VERSION 5.8 ;
BUSBITCHARS "[]" ;
DIVIDERCHAR "/" ;
UNITS
    DATABASE MICRONS 1000 ;
END UNITS

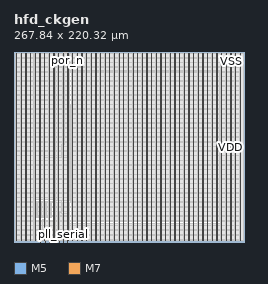
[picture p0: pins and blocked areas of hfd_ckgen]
MACRO hfd_ckgen
  FOREIGN hfd_ckgen 0 0 ;
  CLASS BLOCK ;
  SIZE 267.84 BY 220.32 ;
  PIN pll_hbm
    DIRECTION OUTPUT ;
    USE SIGNAL ;
    PORT
      LAYER M5 ;
        RECT  48.048 0 48.072 0.084 ;
    END
  END pll_hbm
  PIN pll_link
    DIRECTION OUTPUT ;
    USE SIGNAL ;
    PORT
      LAYER M5 ;
        RECT  62.448 0 62.472 0.084 ;
    END
  END pll_link
  PIN pll_serial
    DIRECTION OUTPUT ;
    USE SIGNAL ;
    PORT
      LAYER M5 ;
        RECT  57.648 0 57.672 0.084 ;
    END
  END pll_serial
  PIN pll_stream
    DIRECTION OUTPUT ;
    USE SIGNAL ;
    PORT
      LAYER M5 ;
        RECT  52.848 0 52.872 0.084 ;
    END
  END pll_stream
  PIN por_hbm
    DIRECTION OUTPUT ;
    USE SIGNAL ;
    PORT
      LAYER M5 ;
        RECT  31.152 0 31.176 0.084 ;
    END
  END por_hbm
  PIN por_link
    DIRECTION OUTPUT ;
    USE SIGNAL ;
    PORT
      LAYER M5 ;
        RECT  40.848 0 40.872 0.084 ;
    END
  END por_link
  PIN por_n
    DIRECTION INPUT ;
    USE SIGNAL ;
    PORT
      LAYER M5 ;
        RECT  62.352 220.236 62.376 220.32 ;
    END
  END por_n
  PIN por_serial
    DIRECTION OUTPUT ;
    USE SIGNAL ;
    PORT
      LAYER M5 ;
        RECT  36.24 0 36.264 0.084 ;
    END
  END por_serial
  PIN por_stream
    DIRECTION OUTPUT ;
    USE SIGNAL ;
    PORT
      LAYER M5 ;
        RECT  35.952 0 35.976 0.084 ;
    END
  END por_stream
  PIN refclk
    DIRECTION INPUT ;
    USE SIGNAL ;
    PORT
      LAYER M5 ;
        RECT  57.552 220.236 57.576 220.32 ;
    END
  END refclk
  PIN VDD
    DIRECTION INOUT ;
    USE POWER ;
    PORT
      LAYER M7 ;
        RECT  256.816 2.151 257.104 218.169 ;
        RECT  246.016 2.151 246.304 218.169 ;
        RECT  235.216 2.151 235.504 218.169 ;
        RECT  224.416 2.151 224.704 218.169 ;
        RECT  213.616 2.151 213.904 218.169 ;
        RECT  202.816 2.151 203.104 218.169 ;
        RECT  192.016 2.151 192.304 218.169 ;
        RECT  181.216 2.151 181.504 218.169 ;
        RECT  170.416 2.151 170.704 218.169 ;
        RECT  159.616 2.151 159.904 218.169 ;
        RECT  148.816 2.151 149.104 218.169 ;
        RECT  138.016 2.151 138.304 218.169 ;
        RECT  127.216 2.151 127.504 218.169 ;
        RECT  116.416 2.151 116.704 218.169 ;
        RECT  105.616 2.151 105.904 218.169 ;
        RECT  94.816 2.151 95.104 218.169 ;
        RECT  84.016 2.151 84.304 218.169 ;
        RECT  73.216 2.151 73.504 218.169 ;
        RECT  62.416 2.151 62.704 218.169 ;
        RECT  51.616 2.151 51.904 218.169 ;
        RECT  40.816 2.151 41.104 218.169 ;
        RECT  30.016 2.151 30.304 218.169 ;
        RECT  19.216 2.151 19.504 218.169 ;
        RECT  8.416 2.151 8.704 218.169 ;
    END
  END VDD
  PIN VSS
    DIRECTION INOUT ;
    USE GROUND ;
    PORT
      LAYER M7 ;
        RECT  262.216 2.151 262.504 218.169 ;
        RECT  251.416 2.151 251.704 218.169 ;
        RECT  240.616 2.151 240.904 218.169 ;
        RECT  229.816 2.151 230.104 218.169 ;
        RECT  219.016 2.151 219.304 218.169 ;
        RECT  208.216 2.151 208.504 218.169 ;
        RECT  197.416 2.151 197.704 218.169 ;
        RECT  186.616 2.151 186.904 218.169 ;
        RECT  175.816 2.151 176.104 218.169 ;
        RECT  165.016 2.151 165.304 218.169 ;
        RECT  154.216 2.151 154.504 218.169 ;
        RECT  143.416 2.151 143.704 218.169 ;
        RECT  132.616 2.151 132.904 218.169 ;
        RECT  121.816 2.151 122.104 218.169 ;
        RECT  111.016 2.151 111.304 218.169 ;
        RECT  100.216 2.151 100.504 218.169 ;
        RECT  89.416 2.151 89.704 218.169 ;
        RECT  78.616 2.151 78.904 218.169 ;
        RECT  67.816 2.151 68.104 218.169 ;
        RECT  57.016 2.151 57.304 218.169 ;
        RECT  46.216 2.151 46.504 218.169 ;
        RECT  35.416 2.151 35.704 218.169 ;
        RECT  24.616 2.151 24.904 218.169 ;
        RECT  13.816 2.151 14.104 218.169 ;
        RECT  3.016 2.151 3.304 218.169 ;
    END
  END VSS
  OBS
    LAYER RVTN ;
     RECT  2.16 2.16 265.68 2.295 ;
     RECT  2.16 2.565 265.68 2.835 ;
     RECT  2.16 3.105 265.68 3.375 ;
     RECT  2.16 3.645 265.68 3.915 ;
     RECT  2.16 4.185 265.68 4.455 ;
     RECT  2.16 4.725 265.68 4.995 ;
     RECT  2.16 5.265 265.68 5.535 ;
     RECT  2.16 5.805 265.68 6.075 ;
     RECT  2.16 6.345 265.68 6.615 ;
     RECT  2.16 6.885 265.68 7.155 ;
     RECT  2.16 7.425 265.68 7.695 ;
     RECT  2.16 7.965 265.68 8.235 ;
     RECT  2.16 8.505 265.68 8.775 ;
     RECT  2.16 9.045 265.68 9.315 ;
     RECT  2.16 9.585 265.68 9.855 ;
     RECT  2.16 10.125 265.68 10.395 ;
     RECT  2.16 10.665 265.68 10.935 ;
     RECT  2.16 11.205 265.68 11.475 ;
     RECT  2.16 11.745 265.68 12.015 ;
     RECT  2.16 12.285 265.68 12.555 ;
     RECT  2.16 12.825 265.68 13.095 ;
     RECT  2.16 13.365 265.68 13.635 ;
     RECT  2.16 13.905 265.68 14.175 ;
     RECT  2.16 14.445 265.68 14.715 ;
     RECT  2.16 14.985 265.68 15.255 ;
     RECT  2.16 15.525 265.68 15.795 ;
     RECT  2.16 16.065 265.68 16.335 ;
     RECT  2.16 16.605 265.68 16.875 ;
     RECT  2.16 17.145 265.68 17.415 ;
     RECT  2.16 17.685 265.68 17.955 ;
     RECT  2.16 18.225 265.68 18.495 ;
     RECT  2.16 18.765 265.68 19.035 ;
     RECT  2.16 19.305 265.68 19.575 ;
     RECT  2.16 19.845 265.68 20.115 ;
     RECT  2.16 20.385 265.68 20.655 ;
     RECT  2.16 20.925 265.68 21.195 ;
     RECT  2.16 21.465 265.68 21.6 ;
     RECT  2.16 21.6 64.044 21.735 ;
     RECT  240.948 21.6 265.68 21.735 ;
     RECT  2.16 22.005 64.044 22.275 ;
     RECT  240.948 22.005 265.68 22.275 ;
     RECT  2.16 22.545 64.044 22.815 ;
     RECT  240.948 22.545 265.68 22.815 ;
     RECT  2.16 23.085 64.044 23.355 ;
     RECT  240.948 23.085 265.68 23.355 ;
     RECT  2.16 23.625 64.044 23.76 ;
     RECT  2.16 23.76 22.14 23.895 ;
     RECT  47.844 23.76 64.044 23.895 ;
     RECT  240.948 23.625 265.68 23.895 ;
     RECT  2.16 24.165 22.14 24.435 ;
     RECT  47.844 24.165 64.044 24.435 ;
     RECT  240.948 24.165 265.68 24.435 ;
     RECT  2.16 24.705 22.14 24.975 ;
     RECT  47.844 24.705 64.044 24.975 ;
     RECT  240.948 24.705 265.68 24.975 ;
     RECT  2.16 25.245 22.14 25.515 ;
     RECT  47.844 25.245 64.044 25.515 ;
     RECT  240.948 25.245 265.68 25.515 ;
     RECT  2.16 25.785 22.14 26.055 ;
     RECT  47.844 25.785 64.044 26.055 ;
     RECT  240.948 25.785 265.68 26.055 ;
     RECT  2.16 26.325 22.14 26.595 ;
     RECT  47.844 26.325 64.044 26.595 ;
     RECT  240.948 26.325 265.68 26.595 ;
     RECT  2.16 26.865 22.14 27.135 ;
     RECT  47.844 26.865 64.044 27.135 ;
     RECT  240.948 26.865 265.68 27.135 ;
     RECT  2.16 27.405 22.14 27.675 ;
     RECT  47.844 27.405 64.044 27.675 ;
     RECT  240.948 27.405 265.68 27.675 ;
     RECT  2.16 27.945 22.14 28.215 ;
     RECT  26.352 28.08 43.632 28.215 ;
     RECT  47.844 27.945 64.044 28.215 ;
     RECT  240.948 27.945 265.68 28.215 ;
     RECT  2.16 28.485 22.14 28.755 ;
     RECT  26.352 28.485 43.632 28.755 ;
     RECT  47.844 28.485 64.044 28.755 ;
     RECT  240.948 28.485 265.68 28.755 ;
     RECT  2.16 29.025 22.14 29.295 ;
     RECT  26.352 29.025 43.632 29.295 ;
     RECT  47.844 29.025 64.044 29.295 ;
     RECT  240.948 29.025 265.68 29.295 ;
     RECT  2.16 29.565 22.14 29.835 ;
     RECT  26.352 29.565 43.632 29.835 ;
     RECT  47.844 29.565 64.044 29.835 ;
     RECT  240.948 29.565 265.68 29.835 ;
     RECT  2.16 30.105 22.14 30.375 ;
     RECT  26.352 30.105 43.632 30.375 ;
     RECT  47.844 30.105 64.044 30.375 ;
     RECT  240.948 30.105 265.68 30.375 ;
     RECT  2.16 30.645 22.14 30.915 ;
     RECT  26.352 30.645 43.632 30.915 ;
     RECT  47.844 30.645 64.044 30.915 ;
     RECT  240.948 30.645 265.68 30.915 ;
     RECT  2.16 31.185 22.14 31.455 ;
     RECT  26.352 31.185 43.632 31.455 ;
     RECT  47.844 31.185 64.044 31.455 ;
     RECT  240.948 31.185 265.68 31.455 ;
     RECT  2.16 31.725 22.14 31.995 ;
     RECT  26.352 31.725 43.632 31.995 ;
     RECT  47.844 31.725 64.044 31.995 ;
     RECT  240.948 31.725 265.68 31.995 ;
     RECT  2.16 32.265 22.14 32.535 ;
     RECT  26.352 32.265 43.632 32.535 ;
     RECT  47.844 32.265 64.044 32.535 ;
     RECT  240.948 32.265 265.68 32.535 ;
     RECT  2.16 32.805 22.14 33.075 ;
     RECT  26.352 32.805 43.632 33.075 ;
     RECT  47.844 32.805 64.044 33.075 ;
     RECT  240.948 32.805 265.68 33.075 ;
     RECT  2.16 33.345 22.14 33.615 ;
     RECT  26.352 33.345 43.632 33.615 ;
     RECT  47.844 33.345 64.044 33.615 ;
     RECT  240.948 33.345 265.68 33.615 ;
     RECT  2.16 33.885 22.14 34.155 ;
     RECT  26.352 33.885 43.632 34.155 ;
     RECT  47.844 33.885 64.044 34.155 ;
     RECT  240.948 33.885 265.68 34.155 ;
     RECT  2.16 34.425 22.14 34.695 ;
     RECT  26.352 34.425 43.632 34.695 ;
     RECT  47.844 34.425 64.044 34.695 ;
     RECT  240.948 34.425 265.68 34.695 ;
     RECT  2.16 34.965 22.14 35.235 ;
     RECT  26.352 34.965 43.632 35.235 ;
     RECT  47.844 34.965 64.044 35.235 ;
     RECT  240.948 34.965 265.68 35.235 ;
     RECT  2.16 35.505 22.14 35.775 ;
     RECT  26.352 35.505 43.632 35.775 ;
     RECT  47.844 35.505 64.044 35.775 ;
     RECT  240.948 35.505 265.68 35.775 ;
     RECT  2.16 36.045 22.14 36.315 ;
     RECT  26.352 36.045 43.632 36.315 ;
     RECT  47.844 36.045 64.044 36.315 ;
     RECT  240.948 36.045 265.68 36.315 ;
     RECT  2.16 36.585 22.14 36.855 ;
     RECT  26.352 36.585 43.632 36.855 ;
     RECT  47.844 36.585 64.044 36.855 ;
     RECT  240.948 36.585 265.68 36.855 ;
     RECT  2.16 37.125 22.14 37.395 ;
     RECT  26.352 37.125 43.632 37.395 ;
     RECT  47.844 37.125 64.044 37.395 ;
     RECT  240.948 37.125 265.68 37.395 ;
     RECT  2.16 37.665 22.14 37.935 ;
     RECT  26.352 37.665 43.632 37.935 ;
     RECT  47.844 37.665 64.044 37.935 ;
     RECT  240.948 37.665 265.68 37.935 ;
     RECT  2.16 38.205 22.14 38.475 ;
     RECT  26.352 38.205 43.632 38.475 ;
     RECT  47.844 38.205 64.044 38.475 ;
     RECT  240.948 38.205 265.68 38.475 ;
     RECT  2.16 38.745 22.14 39.015 ;
     RECT  26.352 38.745 43.632 39.015 ;
     RECT  47.844 38.745 64.044 39.015 ;
     RECT  240.948 38.745 265.68 39.015 ;
     RECT  2.16 39.285 22.14 39.555 ;
     RECT  26.352 39.285 43.632 39.555 ;
     RECT  47.844 39.285 64.044 39.555 ;
     RECT  240.948 39.285 265.68 39.555 ;
     RECT  2.16 39.825 22.14 40.095 ;
     RECT  26.352 39.825 43.632 40.095 ;
     RECT  47.844 39.825 64.044 40.095 ;
     RECT  240.948 39.825 265.68 40.095 ;
     RECT  2.16 40.365 22.14 40.635 ;
     RECT  26.352 40.365 43.632 40.635 ;
     RECT  47.844 40.365 64.044 40.635 ;
     RECT  240.948 40.365 265.68 40.635 ;
     RECT  2.16 40.905 22.14 41.175 ;
     RECT  26.352 40.905 43.632 41.175 ;
     RECT  47.844 40.905 64.044 41.175 ;
     RECT  240.948 40.905 265.68 41.175 ;
     RECT  2.16 41.445 22.14 41.715 ;
     RECT  26.352 41.445 43.632 41.715 ;
     RECT  47.844 41.445 64.044 41.715 ;
     RECT  240.948 41.445 265.68 41.715 ;
     RECT  2.16 41.985 22.14 42.255 ;
     RECT  26.352 41.985 43.632 42.255 ;
     RECT  47.844 41.985 64.044 42.255 ;
     RECT  240.948 41.985 265.68 42.255 ;
     RECT  2.16 42.525 22.14 42.795 ;
     RECT  26.352 42.525 43.632 42.795 ;
     RECT  47.844 42.525 64.044 42.795 ;
     RECT  240.948 42.525 265.68 42.795 ;
     RECT  2.16 43.065 22.14 43.335 ;
     RECT  26.352 43.065 43.632 43.335 ;
     RECT  47.844 43.065 64.044 43.335 ;
     RECT  240.948 43.065 265.68 43.335 ;
     RECT  2.16 43.605 22.14 43.875 ;
     RECT  26.352 43.605 43.632 43.875 ;
     RECT  47.844 43.605 64.044 43.875 ;
     RECT  240.948 43.605 265.68 43.875 ;
     RECT  2.16 44.145 22.14 44.415 ;
     RECT  26.352 44.145 43.632 44.415 ;
     RECT  47.844 44.145 64.044 44.415 ;
     RECT  240.948 44.145 265.68 44.415 ;
     RECT  2.16 44.685 22.14 44.955 ;
     RECT  26.352 44.685 43.632 44.955 ;
     RECT  47.844 44.685 64.044 44.955 ;
     RECT  240.948 44.685 265.68 44.955 ;
     RECT  26.352 45.225 43.632 45.36 ;
     RECT  2.16 45.225 22.14 45.495 ;
     RECT  47.844 45.225 64.044 45.495 ;
     RECT  240.948 45.225 265.68 45.495 ;
     RECT  2.16 45.765 22.14 46.035 ;
     RECT  47.844 45.765 64.044 46.035 ;
     RECT  240.948 45.765 265.68 46.035 ;
     RECT  2.16 46.305 22.14 46.575 ;
     RECT  47.844 46.305 64.044 46.575 ;
     RECT  240.948 46.305 265.68 46.575 ;
     RECT  2.16 46.845 22.14 47.115 ;
     RECT  47.844 46.845 64.044 47.115 ;
     RECT  240.948 46.845 265.68 47.115 ;
     RECT  2.16 47.385 22.14 47.655 ;
     RECT  47.844 47.385 64.044 47.655 ;
     RECT  240.948 47.385 265.68 47.655 ;
     RECT  2.16 47.925 22.14 48.195 ;
     RECT  47.844 47.925 64.044 48.195 ;
     RECT  240.948 47.925 265.68 48.195 ;
     RECT  2.16 48.465 22.14 48.735 ;
     RECT  47.844 48.465 64.044 48.735 ;
     RECT  240.948 48.465 265.68 48.735 ;
     RECT  2.16 49.005 22.14 49.275 ;
     RECT  47.844 49.005 64.044 49.275 ;
     RECT  240.948 49.005 265.68 49.275 ;
     RECT  2.16 49.545 22.14 49.68 ;
     RECT  47.844 49.545 64.044 49.68 ;
     RECT  2.16 49.68 64.044 49.815 ;
     RECT  240.948 49.545 265.68 49.815 ;
     RECT  2.16 50.085 64.044 50.355 ;
     RECT  240.948 50.085 265.68 50.355 ;
     RECT  2.16 50.625 64.044 50.895 ;
     RECT  240.948 50.625 265.68 50.895 ;
     RECT  2.16 51.165 64.044 51.435 ;
     RECT  240.948 51.165 265.68 51.435 ;
     RECT  2.16 51.705 64.044 51.975 ;
     RECT  240.948 51.705 265.68 51.975 ;
     RECT  2.16 52.245 64.044 52.515 ;
     RECT  240.948 52.245 265.68 52.515 ;
     RECT  2.16 52.785 64.044 53.055 ;
     RECT  240.948 52.785 265.68 53.055 ;
     RECT  2.16 53.325 64.044 53.595 ;
     RECT  240.948 53.325 265.68 53.595 ;
     RECT  2.16 53.865 64.044 54.135 ;
     RECT  240.948 53.865 265.68 54.135 ;
     RECT  2.16 54.405 64.044 54.675 ;
     RECT  240.948 54.405 265.68 54.675 ;
     RECT  2.16 54.945 64.044 55.215 ;
     RECT  240.948 54.945 265.68 55.215 ;
     RECT  2.16 55.485 64.044 55.755 ;
     RECT  240.948 55.485 265.68 55.755 ;
     RECT  2.16 56.025 64.044 56.295 ;
     RECT  240.948 56.025 265.68 56.295 ;
     RECT  2.16 56.565 64.044 56.835 ;
     RECT  240.948 56.565 265.68 56.835 ;
     RECT  2.16 57.105 64.044 57.375 ;
     RECT  240.948 57.105 265.68 57.375 ;
     RECT  2.16 57.645 64.044 57.915 ;
     RECT  240.948 57.645 265.68 57.915 ;
     RECT  2.16 58.185 64.044 58.455 ;
     RECT  240.948 58.185 265.68 58.455 ;
     RECT  2.16 58.725 64.044 58.995 ;
     RECT  240.948 58.725 265.68 58.995 ;
     RECT  2.16 59.265 64.044 59.535 ;
     RECT  240.948 59.265 265.68 59.535 ;
     RECT  2.16 59.805 64.044 60.075 ;
     RECT  240.948 59.805 265.68 60.075 ;
     RECT  2.16 60.345 64.044 60.615 ;
     RECT  240.948 60.345 265.68 60.615 ;
     RECT  2.16 60.885 64.044 61.155 ;
     RECT  240.948 60.885 265.68 61.155 ;
     RECT  2.16 61.425 64.044 61.695 ;
     RECT  240.948 61.425 265.68 61.695 ;
     RECT  2.16 61.965 64.044 62.235 ;
     RECT  240.948 61.965 265.68 62.235 ;
     RECT  2.16 62.505 64.044 62.775 ;
     RECT  240.948 62.505 265.68 62.775 ;
     RECT  2.16 63.045 64.044 63.315 ;
     RECT  240.948 63.045 265.68 63.315 ;
     RECT  2.16 63.585 64.044 63.855 ;
     RECT  240.948 63.585 265.68 63.855 ;
     RECT  2.16 64.125 64.044 64.395 ;
     RECT  240.948 64.125 265.68 64.395 ;
     RECT  2.16 64.665 64.044 64.935 ;
     RECT  240.948 64.665 265.68 64.935 ;
     RECT  2.16 65.205 64.044 65.475 ;
     RECT  240.948 65.205 265.68 65.475 ;
     RECT  2.16 65.745 64.044 66.015 ;
     RECT  240.948 65.745 265.68 66.015 ;
     RECT  2.16 66.285 64.044 66.555 ;
     RECT  240.948 66.285 265.68 66.555 ;
     RECT  2.16 66.825 64.044 67.095 ;
     RECT  240.948 66.825 265.68 67.095 ;
     RECT  2.16 67.365 64.044 67.635 ;
     RECT  240.948 67.365 265.68 67.635 ;
     RECT  2.16 67.905 64.044 68.175 ;
     RECT  240.948 67.905 265.68 68.175 ;
     RECT  2.16 68.445 64.044 68.715 ;
     RECT  240.948 68.445 265.68 68.715 ;
     RECT  2.16 68.985 64.044 69.255 ;
     RECT  240.948 68.985 265.68 69.255 ;
     RECT  2.16 69.525 64.044 69.795 ;
     RECT  240.948 69.525 265.68 69.795 ;
     RECT  2.16 70.065 64.044 70.335 ;
     RECT  240.948 70.065 265.68 70.335 ;
     RECT  2.16 70.605 64.044 70.875 ;
     RECT  240.948 70.605 265.68 70.875 ;
     RECT  2.16 71.145 64.044 71.415 ;
     RECT  240.948 71.145 265.68 71.415 ;
     RECT  2.16 71.685 64.044 71.955 ;
     RECT  240.948 71.685 265.68 71.955 ;
     RECT  2.16 72.225 64.044 72.495 ;
     RECT  240.948 72.225 265.68 72.495 ;
     RECT  2.16 72.765 64.044 73.035 ;
     RECT  240.948 72.765 265.68 73.035 ;
     RECT  2.16 73.305 64.044 73.575 ;
     RECT  240.948 73.305 265.68 73.575 ;
     RECT  2.16 73.845 64.044 74.115 ;
     RECT  240.948 73.845 265.68 74.115 ;
     RECT  2.16 74.385 64.044 74.655 ;
     RECT  240.948 74.385 265.68 74.655 ;
     RECT  2.16 74.925 64.044 75.195 ;
     RECT  240.948 74.925 265.68 75.195 ;
     RECT  2.16 75.465 64.044 75.735 ;
     RECT  240.948 75.465 265.68 75.735 ;
     RECT  2.16 76.005 64.044 76.275 ;
     RECT  240.948 76.005 265.68 76.275 ;
     RECT  2.16 76.545 64.044 76.815 ;
     RECT  240.948 76.545 265.68 76.815 ;
     RECT  2.16 77.085 64.044 77.355 ;
     RECT  240.948 77.085 265.68 77.355 ;
     RECT  2.16 77.625 64.044 77.895 ;
     RECT  240.948 77.625 265.68 77.895 ;
     RECT  2.16 78.165 64.044 78.435 ;
     RECT  240.948 78.165 265.68 78.435 ;
     RECT  2.16 78.705 64.044 78.975 ;
     RECT  240.948 78.705 265.68 78.975 ;
     RECT  2.16 79.245 64.044 79.515 ;
     RECT  240.948 79.245 265.68 79.515 ;
     RECT  2.16 79.785 64.044 80.055 ;
     RECT  240.948 79.785 265.68 80.055 ;
     RECT  2.16 80.325 64.044 80.595 ;
     RECT  240.948 80.325 265.68 80.595 ;
     RECT  2.16 80.865 64.044 81.135 ;
     RECT  240.948 80.865 265.68 81.135 ;
     RECT  2.16 81.405 64.044 81.675 ;
     RECT  240.948 81.405 265.68 81.675 ;
     RECT  2.16 81.945 64.044 82.215 ;
     RECT  240.948 81.945 265.68 82.215 ;
     RECT  2.16 82.485 64.044 82.755 ;
     RECT  240.948 82.485 265.68 82.755 ;
     RECT  2.16 83.025 64.044 83.295 ;
     RECT  240.948 83.025 265.68 83.295 ;
     RECT  2.16 83.565 64.044 83.835 ;
     RECT  240.948 83.565 265.68 83.835 ;
     RECT  2.16 84.105 64.044 84.375 ;
     RECT  240.948 84.105 265.68 84.375 ;
     RECT  2.16 84.645 64.044 84.915 ;
     RECT  240.948 84.645 265.68 84.915 ;
     RECT  2.16 85.185 64.044 85.455 ;
     RECT  240.948 85.185 265.68 85.455 ;
     RECT  2.16 85.725 64.044 85.995 ;
     RECT  240.948 85.725 265.68 85.995 ;
     RECT  2.16 86.265 64.044 86.535 ;
     RECT  240.948 86.265 265.68 86.535 ;
     RECT  2.16 86.805 64.044 87.075 ;
     RECT  240.948 86.805 265.68 87.075 ;
     RECT  2.16 87.345 64.044 87.615 ;
     RECT  240.948 87.345 265.68 87.615 ;
     RECT  2.16 87.885 64.044 88.155 ;
     RECT  240.948 87.885 265.68 88.155 ;
     RECT  2.16 88.425 64.044 88.695 ;
     RECT  240.948 88.425 265.68 88.695 ;
     RECT  2.16 88.965 64.044 89.235 ;
     RECT  240.948 88.965 265.68 89.235 ;
     RECT  2.16 89.505 64.044 89.775 ;
     RECT  240.948 89.505 265.68 89.775 ;
     RECT  2.16 90.045 64.044 90.315 ;
     RECT  240.948 90.045 265.68 90.315 ;
     RECT  2.16 90.585 64.044 90.855 ;
     RECT  240.948 90.585 265.68 90.855 ;
     RECT  2.16 91.125 64.044 91.395 ;
     RECT  240.948 91.125 265.68 91.395 ;
     RECT  2.16 91.665 64.044 91.935 ;
     RECT  240.948 91.665 265.68 91.935 ;
     RECT  2.16 92.205 64.044 92.475 ;
     RECT  240.948 92.205 265.68 92.475 ;
     RECT  2.16 92.745 64.044 93.015 ;
     RECT  240.948 92.745 265.68 93.015 ;
     RECT  2.16 93.285 64.044 93.555 ;
     RECT  240.948 93.285 265.68 93.555 ;
     RECT  2.16 93.825 64.044 94.095 ;
     RECT  240.948 93.825 265.68 94.095 ;
     RECT  2.16 94.365 64.044 94.635 ;
     RECT  240.948 94.365 265.68 94.635 ;
     RECT  2.16 94.905 64.044 95.175 ;
     RECT  240.948 94.905 265.68 95.175 ;
     RECT  2.16 95.445 64.044 95.715 ;
     RECT  240.948 95.445 265.68 95.715 ;
     RECT  2.16 95.985 64.044 96.255 ;
     RECT  240.948 95.985 265.68 96.255 ;
     RECT  2.16 96.525 64.044 96.795 ;
     RECT  240.948 96.525 265.68 96.795 ;
     RECT  2.16 97.065 64.044 97.335 ;
     RECT  240.948 97.065 265.68 97.335 ;
     RECT  2.16 97.605 64.044 97.875 ;
     RECT  240.948 97.605 265.68 97.875 ;
     RECT  2.16 98.145 64.044 98.415 ;
     RECT  240.948 98.145 265.68 98.415 ;
     RECT  2.16 98.685 64.044 98.955 ;
     RECT  240.948 98.685 265.68 98.955 ;
     RECT  2.16 99.225 64.044 99.495 ;
     RECT  240.948 99.225 265.68 99.495 ;
     RECT  2.16 99.765 64.044 100.035 ;
     RECT  240.948 99.765 265.68 100.035 ;
     RECT  2.16 100.305 64.044 100.575 ;
     RECT  240.948 100.305 265.68 100.575 ;
     RECT  2.16 100.845 64.044 101.115 ;
     RECT  240.948 100.845 265.68 101.115 ;
     RECT  2.16 101.385 64.044 101.655 ;
     RECT  240.948 101.385 265.68 101.655 ;
     RECT  2.16 101.925 64.044 102.195 ;
     RECT  240.948 101.925 265.68 102.195 ;
     RECT  2.16 102.465 64.044 102.735 ;
     RECT  240.948 102.465 265.68 102.735 ;
     RECT  2.16 103.005 64.044 103.275 ;
     RECT  240.948 103.005 265.68 103.275 ;
     RECT  2.16 103.545 64.044 103.815 ;
     RECT  240.948 103.545 265.68 103.815 ;
     RECT  2.16 104.085 64.044 104.355 ;
     RECT  240.948 104.085 265.68 104.355 ;
     RECT  2.16 104.625 64.044 104.895 ;
     RECT  240.948 104.625 265.68 104.895 ;
     RECT  2.16 105.165 64.044 105.435 ;
     RECT  240.948 105.165 265.68 105.435 ;
     RECT  2.16 105.705 64.044 105.975 ;
     RECT  240.948 105.705 265.68 105.975 ;
     RECT  2.16 106.245 64.044 106.515 ;
     RECT  240.948 106.245 265.68 106.515 ;
     RECT  2.16 106.785 64.044 107.055 ;
     RECT  240.948 106.785 265.68 107.055 ;
     RECT  2.16 107.325 64.044 107.595 ;
     RECT  240.948 107.325 265.68 107.595 ;
     RECT  2.16 107.865 64.044 108.135 ;
     RECT  240.948 107.865 265.68 108.135 ;
     RECT  2.16 108.405 64.044 108.675 ;
     RECT  240.948 108.405 265.68 108.675 ;
     RECT  2.16 108.945 64.044 109.215 ;
     RECT  240.948 108.945 265.68 109.215 ;
     RECT  2.16 109.485 64.044 109.755 ;
     RECT  240.948 109.485 265.68 109.755 ;
     RECT  2.16 110.025 64.044 110.295 ;
     RECT  240.948 110.025 265.68 110.295 ;
     RECT  2.16 110.565 64.044 110.835 ;
     RECT  240.948 110.565 265.68 110.835 ;
     RECT  2.16 111.105 64.044 111.375 ;
     RECT  240.948 111.105 265.68 111.375 ;
     RECT  2.16 111.645 64.044 111.915 ;
     RECT  240.948 111.645 265.68 111.915 ;
     RECT  2.16 112.185 64.044 112.455 ;
     RECT  240.948 112.185 265.68 112.455 ;
     RECT  2.16 112.725 64.044 112.995 ;
     RECT  240.948 112.725 265.68 112.995 ;
     RECT  2.16 113.265 64.044 113.535 ;
     RECT  240.948 113.265 265.68 113.535 ;
     RECT  2.16 113.805 64.044 114.075 ;
     RECT  240.948 113.805 265.68 114.075 ;
     RECT  2.16 114.345 64.044 114.615 ;
     RECT  240.948 114.345 265.68 114.615 ;
     RECT  2.16 114.885 64.044 115.155 ;
     RECT  240.948 114.885 265.68 115.155 ;
     RECT  2.16 115.425 64.044 115.695 ;
     RECT  240.948 115.425 265.68 115.695 ;
     RECT  2.16 115.965 64.044 116.235 ;
     RECT  240.948 115.965 265.68 116.235 ;
     RECT  2.16 116.505 64.044 116.775 ;
     RECT  240.948 116.505 265.68 116.775 ;
     RECT  2.16 117.045 64.044 117.315 ;
     RECT  240.948 117.045 265.68 117.315 ;
     RECT  2.16 117.585 64.044 117.855 ;
     RECT  240.948 117.585 265.68 117.855 ;
     RECT  2.16 118.125 64.044 118.395 ;
     RECT  240.948 118.125 265.68 118.395 ;
     RECT  2.16 118.665 64.044 118.935 ;
     RECT  240.948 118.665 265.68 118.935 ;
     RECT  2.16 119.205 64.044 119.475 ;
     RECT  240.948 119.205 265.68 119.475 ;
     RECT  2.16 119.745 64.044 120.015 ;
     RECT  240.948 119.745 265.68 120.015 ;
     RECT  2.16 120.285 64.044 120.555 ;
     RECT  240.948 120.285 265.68 120.555 ;
     RECT  2.16 120.825 64.044 121.095 ;
     RECT  240.948 120.825 265.68 121.095 ;
     RECT  2.16 121.365 64.044 121.635 ;
     RECT  240.948 121.365 265.68 121.635 ;
     RECT  2.16 121.905 64.044 122.175 ;
     RECT  240.948 121.905 265.68 122.175 ;
     RECT  2.16 122.445 64.044 122.715 ;
     RECT  240.948 122.445 265.68 122.715 ;
     RECT  2.16 122.985 64.044 123.255 ;
     RECT  240.948 122.985 265.68 123.255 ;
     RECT  2.16 123.525 64.044 123.795 ;
     RECT  240.948 123.525 265.68 123.795 ;
     RECT  2.16 124.065 64.044 124.335 ;
     RECT  240.948 124.065 265.68 124.335 ;
     RECT  2.16 124.605 64.044 124.875 ;
     RECT  240.948 124.605 265.68 124.875 ;
     RECT  2.16 125.145 64.044 125.415 ;
     RECT  240.948 125.145 265.68 125.415 ;
     RECT  2.16 125.685 64.044 125.955 ;
     RECT  240.948 125.685 265.68 125.955 ;
     RECT  2.16 126.225 64.044 126.495 ;
     RECT  240.948 126.225 265.68 126.495 ;
     RECT  2.16 126.765 64.044 127.035 ;
     RECT  240.948 126.765 265.68 127.035 ;
     RECT  2.16 127.305 64.044 127.575 ;
     RECT  240.948 127.305 265.68 127.575 ;
     RECT  2.16 127.845 64.044 128.115 ;
     RECT  240.948 127.845 265.68 128.115 ;
     RECT  2.16 128.385 64.044 128.655 ;
     RECT  240.948 128.385 265.68 128.655 ;
     RECT  2.16 128.925 64.044 129.195 ;
     RECT  240.948 128.925 265.68 129.195 ;
     RECT  2.16 129.465 64.044 129.735 ;
     RECT  240.948 129.465 265.68 129.735 ;
     RECT  2.16 130.005 64.044 130.275 ;
     RECT  240.948 130.005 265.68 130.275 ;
     RECT  2.16 130.545 64.044 130.815 ;
     RECT  240.948 130.545 265.68 130.815 ;
     RECT  2.16 131.085 64.044 131.355 ;
     RECT  240.948 131.085 265.68 131.355 ;
     RECT  2.16 131.625 64.044 131.895 ;
     RECT  240.948 131.625 265.68 131.895 ;
     RECT  2.16 132.165 64.044 132.435 ;
     RECT  240.948 132.165 265.68 132.435 ;
     RECT  2.16 132.705 64.044 132.975 ;
     RECT  240.948 132.705 265.68 132.975 ;
     RECT  2.16 133.245 64.044 133.515 ;
     RECT  240.948 133.245 265.68 133.515 ;
     RECT  2.16 133.785 64.044 134.055 ;
     RECT  240.948 133.785 265.68 134.055 ;
     RECT  2.16 134.325 64.044 134.595 ;
     RECT  240.948 134.325 265.68 134.595 ;
     RECT  2.16 134.865 64.044 135.135 ;
     RECT  240.948 134.865 265.68 135.135 ;
     RECT  2.16 135.405 64.044 135.675 ;
     RECT  240.948 135.405 265.68 135.675 ;
     RECT  2.16 135.945 64.044 136.215 ;
     RECT  240.948 135.945 265.68 136.215 ;
     RECT  2.16 136.485 64.044 136.755 ;
     RECT  240.948 136.485 265.68 136.755 ;
     RECT  2.16 137.025 64.044 137.295 ;
     RECT  240.948 137.025 265.68 137.295 ;
     RECT  2.16 137.565 64.044 137.835 ;
     RECT  240.948 137.565 265.68 137.835 ;
     RECT  2.16 138.105 64.044 138.375 ;
     RECT  240.948 138.105 265.68 138.375 ;
     RECT  2.16 138.645 64.044 138.915 ;
     RECT  240.948 138.645 265.68 138.915 ;
     RECT  2.16 139.185 64.044 139.455 ;
     RECT  240.948 139.185 265.68 139.455 ;
     RECT  2.16 139.725 64.044 139.995 ;
     RECT  240.948 139.725 265.68 139.995 ;
     RECT  2.16 140.265 64.044 140.535 ;
     RECT  240.948 140.265 265.68 140.535 ;
     RECT  2.16 140.805 64.044 141.075 ;
     RECT  240.948 140.805 265.68 141.075 ;
     RECT  2.16 141.345 64.044 141.615 ;
     RECT  240.948 141.345 265.68 141.615 ;
     RECT  2.16 141.885 64.044 142.155 ;
     RECT  240.948 141.885 265.68 142.155 ;
     RECT  2.16 142.425 64.044 142.695 ;
     RECT  240.948 142.425 265.68 142.695 ;
     RECT  2.16 142.965 64.044 143.235 ;
     RECT  240.948 142.965 265.68 143.235 ;
     RECT  2.16 143.505 64.044 143.775 ;
     RECT  240.948 143.505 265.68 143.775 ;
     RECT  2.16 144.045 64.044 144.315 ;
     RECT  240.948 144.045 265.68 144.315 ;
     RECT  2.16 144.585 64.044 144.855 ;
     RECT  240.948 144.585 265.68 144.855 ;
     RECT  2.16 145.125 64.044 145.395 ;
     RECT  240.948 145.125 265.68 145.395 ;
     RECT  2.16 145.665 64.044 145.935 ;
     RECT  240.948 145.665 265.68 145.935 ;
     RECT  2.16 146.205 64.044 146.475 ;
     RECT  240.948 146.205 265.68 146.475 ;
     RECT  2.16 146.745 64.044 147.015 ;
     RECT  240.948 146.745 265.68 147.015 ;
     RECT  2.16 147.285 64.044 147.555 ;
     RECT  240.948 147.285 265.68 147.555 ;
     RECT  2.16 147.825 64.044 148.095 ;
     RECT  240.948 147.825 265.68 148.095 ;
     RECT  2.16 148.365 64.044 148.635 ;
     RECT  240.948 148.365 265.68 148.635 ;
     RECT  2.16 148.905 64.044 149.175 ;
     RECT  240.948 148.905 265.68 149.175 ;
     RECT  2.16 149.445 64.044 149.715 ;
     RECT  240.948 149.445 265.68 149.715 ;
     RECT  2.16 149.985 64.044 150.255 ;
     RECT  240.948 149.985 265.68 150.255 ;
     RECT  2.16 150.525 64.044 150.795 ;
     RECT  240.948 150.525 265.68 150.795 ;
     RECT  2.16 151.065 64.044 151.335 ;
     RECT  240.948 151.065 265.68 151.335 ;
     RECT  2.16 151.605 64.044 151.875 ;
     RECT  240.948 151.605 265.68 151.875 ;
     RECT  2.16 152.145 64.044 152.415 ;
     RECT  240.948 152.145 265.68 152.415 ;
     RECT  2.16 152.685 64.044 152.955 ;
     RECT  240.948 152.685 265.68 152.955 ;
     RECT  2.16 153.225 64.044 153.495 ;
     RECT  240.948 153.225 265.68 153.495 ;
     RECT  2.16 153.765 64.044 154.035 ;
     RECT  240.948 153.765 265.68 154.035 ;
     RECT  2.16 154.305 64.044 154.575 ;
     RECT  240.948 154.305 265.68 154.575 ;
     RECT  2.16 154.845 64.044 155.115 ;
     RECT  240.948 154.845 265.68 155.115 ;
     RECT  2.16 155.385 64.044 155.655 ;
     RECT  240.948 155.385 265.68 155.655 ;
     RECT  2.16 155.925 64.044 156.195 ;
     RECT  240.948 155.925 265.68 156.195 ;
     RECT  2.16 156.465 64.044 156.735 ;
     RECT  240.948 156.465 265.68 156.735 ;
     RECT  2.16 157.005 64.044 157.275 ;
     RECT  240.948 157.005 265.68 157.275 ;
     RECT  2.16 157.545 64.044 157.815 ;
     RECT  240.948 157.545 265.68 157.815 ;
     RECT  2.16 158.085 64.044 158.355 ;
     RECT  240.948 158.085 265.68 158.355 ;
     RECT  2.16 158.625 64.044 158.895 ;
     RECT  240.948 158.625 265.68 158.895 ;
     RECT  2.16 159.165 64.044 159.435 ;
     RECT  240.948 159.165 265.68 159.435 ;
     RECT  2.16 159.705 64.044 159.975 ;
     RECT  240.948 159.705 265.68 159.975 ;
     RECT  2.16 160.245 64.044 160.515 ;
     RECT  240.948 160.245 265.68 160.515 ;
     RECT  2.16 160.785 64.044 161.055 ;
     RECT  240.948 160.785 265.68 161.055 ;
     RECT  2.16 161.325 64.044 161.595 ;
     RECT  240.948 161.325 265.68 161.595 ;
     RECT  2.16 161.865 64.044 162.135 ;
     RECT  240.948 161.865 265.68 162.135 ;
     RECT  2.16 162.405 64.044 162.675 ;
     RECT  240.948 162.405 265.68 162.675 ;
     RECT  2.16 162.945 64.044 163.215 ;
     RECT  240.948 162.945 265.68 163.215 ;
     RECT  2.16 163.485 64.044 163.755 ;
     RECT  240.948 163.485 265.68 163.755 ;
     RECT  2.16 164.025 64.044 164.295 ;
     RECT  240.948 164.025 265.68 164.295 ;
     RECT  2.16 164.565 64.044 164.835 ;
     RECT  240.948 164.565 265.68 164.835 ;
     RECT  2.16 165.105 64.044 165.375 ;
     RECT  240.948 165.105 265.68 165.375 ;
     RECT  2.16 165.645 64.044 165.915 ;
     RECT  240.948 165.645 265.68 165.915 ;
     RECT  2.16 166.185 64.044 166.455 ;
     RECT  240.948 166.185 265.68 166.455 ;
     RECT  2.16 166.725 64.044 166.995 ;
     RECT  240.948 166.725 265.68 166.995 ;
     RECT  2.16 167.265 64.044 167.535 ;
     RECT  240.948 167.265 265.68 167.535 ;
     RECT  2.16 167.805 64.044 168.075 ;
     RECT  240.948 167.805 265.68 168.075 ;
     RECT  2.16 168.345 64.044 168.615 ;
     RECT  240.948 168.345 265.68 168.615 ;
     RECT  2.16 168.885 64.044 169.155 ;
     RECT  240.948 168.885 265.68 169.155 ;
     RECT  2.16 169.425 64.044 169.695 ;
     RECT  240.948 169.425 265.68 169.695 ;
     RECT  2.16 169.965 64.044 170.235 ;
     RECT  240.948 169.965 265.68 170.235 ;
     RECT  2.16 170.505 64.044 170.775 ;
     RECT  240.948 170.505 265.68 170.775 ;
     RECT  2.16 171.045 64.044 171.315 ;
     RECT  240.948 171.045 265.68 171.315 ;
     RECT  2.16 171.585 64.044 171.855 ;
     RECT  240.948 171.585 265.68 171.855 ;
     RECT  2.16 172.125 64.044 172.395 ;
     RECT  240.948 172.125 265.68 172.395 ;
     RECT  2.16 172.665 64.044 172.935 ;
     RECT  240.948 172.665 265.68 172.935 ;
     RECT  2.16 173.205 64.044 173.475 ;
     RECT  240.948 173.205 265.68 173.475 ;
     RECT  2.16 173.745 64.044 174.015 ;
     RECT  240.948 173.745 265.68 174.015 ;
     RECT  2.16 174.285 64.044 174.555 ;
     RECT  240.948 174.285 265.68 174.555 ;
     RECT  2.16 174.825 64.044 175.095 ;
     RECT  240.948 174.825 265.68 175.095 ;
     RECT  2.16 175.365 64.044 175.635 ;
     RECT  240.948 175.365 265.68 175.635 ;
     RECT  2.16 175.905 64.044 176.175 ;
     RECT  240.948 175.905 265.68 176.175 ;
     RECT  2.16 176.445 64.044 176.715 ;
     RECT  240.948 176.445 265.68 176.715 ;
     RECT  2.16 176.985 64.044 177.255 ;
     RECT  240.948 176.985 265.68 177.255 ;
     RECT  2.16 177.525 64.044 177.795 ;
     RECT  240.948 177.525 265.68 177.795 ;
     RECT  2.16 178.065 64.044 178.335 ;
     RECT  240.948 178.065 265.68 178.335 ;
     RECT  2.16 178.605 64.044 178.875 ;
     RECT  240.948 178.605 265.68 178.875 ;
     RECT  2.16 179.145 64.044 179.415 ;
     RECT  240.948 179.145 265.68 179.415 ;
     RECT  2.16 179.685 64.044 179.955 ;
     RECT  240.948 179.685 265.68 179.955 ;
     RECT  2.16 180.225 64.044 180.495 ;
     RECT  240.948 180.225 265.68 180.495 ;
     RECT  2.16 180.765 64.044 181.035 ;
     RECT  240.948 180.765 265.68 181.035 ;
     RECT  2.16 181.305 64.044 181.575 ;
     RECT  240.948 181.305 265.68 181.575 ;
     RECT  2.16 181.845 64.044 182.115 ;
     RECT  240.948 181.845 265.68 182.115 ;
     RECT  2.16 182.385 64.044 182.655 ;
     RECT  240.948 182.385 265.68 182.655 ;
     RECT  2.16 182.925 64.044 183.195 ;
     RECT  240.948 182.925 265.68 183.195 ;
     RECT  2.16 183.465 64.044 183.735 ;
     RECT  240.948 183.465 265.68 183.735 ;
     RECT  2.16 184.005 64.044 184.275 ;
     RECT  240.948 184.005 265.68 184.275 ;
     RECT  2.16 184.545 64.044 184.815 ;
     RECT  240.948 184.545 265.68 184.815 ;
     RECT  2.16 185.085 64.044 185.355 ;
     RECT  240.948 185.085 265.68 185.355 ;
     RECT  2.16 185.625 64.044 185.895 ;
     RECT  240.948 185.625 265.68 185.895 ;
     RECT  2.16 186.165 64.044 186.435 ;
     RECT  240.948 186.165 265.68 186.435 ;
     RECT  2.16 186.705 64.044 186.975 ;
     RECT  240.948 186.705 265.68 186.975 ;
     RECT  2.16 187.245 64.044 187.515 ;
     RECT  240.948 187.245 265.68 187.515 ;
     RECT  2.16 187.785 64.044 188.055 ;
     RECT  240.948 187.785 265.68 188.055 ;
     RECT  2.16 188.325 64.044 188.595 ;
     RECT  240.948 188.325 265.68 188.595 ;
     RECT  2.16 188.865 64.044 189.135 ;
     RECT  240.948 188.865 265.68 189.135 ;
     RECT  2.16 189.405 64.044 189.675 ;
     RECT  240.948 189.405 265.68 189.675 ;
     RECT  2.16 189.945 64.044 190.215 ;
     RECT  240.948 189.945 265.68 190.215 ;
     RECT  2.16 190.485 64.044 190.755 ;
     RECT  240.948 190.485 265.68 190.755 ;
     RECT  2.16 191.025 64.044 191.295 ;
     RECT  240.948 191.025 265.68 191.295 ;
     RECT  2.16 191.565 64.044 191.835 ;
     RECT  240.948 191.565 265.68 191.835 ;
     RECT  2.16 192.105 64.044 192.375 ;
     RECT  240.948 192.105 265.68 192.375 ;
     RECT  2.16 192.645 64.044 192.915 ;
     RECT  240.948 192.645 265.68 192.915 ;
     RECT  2.16 193.185 64.044 193.455 ;
     RECT  240.948 193.185 265.68 193.455 ;
     RECT  2.16 193.725 64.044 193.995 ;
     RECT  240.948 193.725 265.68 193.995 ;
     RECT  2.16 194.265 64.044 194.535 ;
     RECT  240.948 194.265 265.68 194.535 ;
     RECT  2.16 194.805 64.044 195.075 ;
     RECT  240.948 194.805 265.68 195.075 ;
     RECT  2.16 195.345 64.044 195.615 ;
     RECT  240.948 195.345 265.68 195.615 ;
     RECT  2.16 195.885 64.044 196.155 ;
     RECT  240.948 195.885 265.68 196.155 ;
     RECT  2.16 196.425 64.044 196.695 ;
     RECT  240.948 196.425 265.68 196.695 ;
     RECT  2.16 196.965 64.044 197.235 ;
     RECT  240.948 196.965 265.68 197.235 ;
     RECT  2.16 197.505 64.044 197.775 ;
     RECT  240.948 197.505 265.68 197.775 ;
     RECT  2.16 198.045 64.044 198.315 ;
     RECT  240.948 198.045 265.68 198.315 ;
     RECT  2.16 198.585 64.044 198.72 ;
     RECT  240.948 198.585 265.68 198.72 ;
     RECT  2.16 198.72 265.68 198.855 ;
     RECT  2.16 199.125 265.68 199.395 ;
     RECT  2.16 199.665 265.68 199.935 ;
     RECT  2.16 200.205 265.68 200.475 ;
     RECT  2.16 200.745 265.68 201.015 ;
     RECT  2.16 201.285 265.68 201.555 ;
     RECT  2.16 201.825 265.68 202.095 ;
     RECT  2.16 202.365 265.68 202.635 ;
     RECT  2.16 202.905 265.68 203.175 ;
     RECT  2.16 203.445 265.68 203.715 ;
     RECT  2.16 203.985 265.68 204.255 ;
     RECT  2.16 204.525 265.68 204.795 ;
     RECT  2.16 205.065 265.68 205.335 ;
     RECT  2.16 205.605 265.68 205.875 ;
     RECT  2.16 206.145 265.68 206.415 ;
     RECT  2.16 206.685 265.68 206.955 ;
     RECT  2.16 207.225 265.68 207.495 ;
     RECT  2.16 207.765 265.68 208.035 ;
     RECT  2.16 208.305 265.68 208.575 ;
     RECT  2.16 208.845 265.68 209.115 ;
     RECT  2.16 209.385 265.68 209.655 ;
     RECT  2.16 209.925 265.68 210.195 ;
     RECT  2.16 210.465 265.68 210.735 ;
     RECT  2.16 211.005 265.68 211.275 ;
     RECT  2.16 211.545 265.68 211.815 ;
     RECT  2.16 212.085 265.68 212.355 ;
     RECT  2.16 212.625 265.68 212.895 ;
     RECT  2.16 213.165 265.68 213.435 ;
     RECT  2.16 213.705 265.68 213.975 ;
     RECT  2.16 214.245 265.68 214.515 ;
     RECT  2.16 214.785 265.68 215.055 ;
     RECT  2.16 215.325 265.68 215.595 ;
     RECT  2.16 215.865 265.68 216.135 ;
     RECT  2.16 216.405 265.68 216.675 ;
     RECT  2.16 216.945 265.68 217.215 ;
     RECT  2.16 217.485 265.68 217.755 ;
     RECT  2.16 218.025 265.68 218.16 ;
    LAYER RVTP ;
     RECT  2.16 2.295 265.68 2.565 ;
     RECT  2.16 2.835 265.68 3.105 ;
     RECT  2.16 3.375 265.68 3.645 ;
     RECT  2.16 3.915 265.68 4.185 ;
     RECT  2.16 4.455 265.68 4.725 ;
     RECT  2.16 4.995 265.68 5.265 ;
     RECT  2.16 5.535 265.68 5.805 ;
     RECT  2.16 6.075 265.68 6.345 ;
     RECT  2.16 6.615 265.68 6.885 ;
     RECT  2.16 7.155 265.68 7.425 ;
     RECT  2.16 7.695 265.68 7.965 ;
     RECT  2.16 8.235 265.68 8.505 ;
     RECT  2.16 8.775 265.68 9.045 ;
     RECT  2.16 9.315 265.68 9.585 ;
     RECT  2.16 9.855 265.68 10.125 ;
     RECT  2.16 10.395 265.68 10.665 ;
     RECT  2.16 10.935 265.68 11.205 ;
     RECT  2.16 11.475 265.68 11.745 ;
     RECT  2.16 12.015 265.68 12.285 ;
     RECT  2.16 12.555 265.68 12.825 ;
     RECT  2.16 13.095 265.68 13.365 ;
     RECT  2.16 13.635 265.68 13.905 ;
     RECT  2.16 14.175 265.68 14.445 ;
     RECT  2.16 14.715 265.68 14.985 ;
     RECT  2.16 15.255 265.68 15.525 ;
     RECT  2.16 15.795 265.68 16.065 ;
     RECT  2.16 16.335 265.68 16.605 ;
     RECT  2.16 16.875 265.68 17.145 ;
     RECT  2.16 17.415 265.68 17.685 ;
     RECT  2.16 17.955 265.68 18.225 ;
     RECT  2.16 18.495 265.68 18.765 ;
     RECT  2.16 19.035 265.68 19.305 ;
     RECT  2.16 19.575 265.68 19.845 ;
     RECT  2.16 20.115 265.68 20.385 ;
     RECT  2.16 20.655 265.68 20.925 ;
     RECT  2.16 21.195 265.68 21.465 ;
     RECT  2.16 21.735 64.044 22.005 ;
     RECT  240.948 21.735 265.68 22.005 ;
     RECT  2.16 22.275 64.044 22.545 ;
     RECT  240.948 22.275 265.68 22.545 ;
     RECT  2.16 22.815 64.044 23.085 ;
     RECT  240.948 22.815 265.68 23.085 ;
     RECT  2.16 23.355 64.044 23.625 ;
     RECT  240.948 23.355 265.68 23.625 ;
     RECT  2.16 23.895 22.14 24.165 ;
     RECT  47.844 23.895 64.044 24.165 ;
     RECT  240.948 23.895 265.68 24.165 ;
     RECT  2.16 24.435 22.14 24.705 ;
     RECT  47.844 24.435 64.044 24.705 ;
     RECT  240.948 24.435 265.68 24.705 ;
     RECT  2.16 24.975 22.14 25.245 ;
     RECT  47.844 24.975 64.044 25.245 ;
     RECT  240.948 24.975 265.68 25.245 ;
     RECT  2.16 25.515 22.14 25.785 ;
     RECT  47.844 25.515 64.044 25.785 ;
     RECT  240.948 25.515 265.68 25.785 ;
     RECT  2.16 26.055 22.14 26.325 ;
     RECT  47.844 26.055 64.044 26.325 ;
     RECT  240.948 26.055 265.68 26.325 ;
     RECT  2.16 26.595 22.14 26.865 ;
     RECT  47.844 26.595 64.044 26.865 ;
     RECT  240.948 26.595 265.68 26.865 ;
     RECT  2.16 27.135 22.14 27.405 ;
     RECT  47.844 27.135 64.044 27.405 ;
     RECT  240.948 27.135 265.68 27.405 ;
     RECT  2.16 27.675 22.14 27.945 ;
     RECT  47.844 27.675 64.044 27.945 ;
     RECT  240.948 27.675 265.68 27.945 ;
     RECT  2.16 28.215 22.14 28.485 ;
     RECT  26.352 28.215 43.632 28.485 ;
     RECT  47.844 28.215 64.044 28.485 ;
     RECT  240.948 28.215 265.68 28.485 ;
     RECT  2.16 28.755 22.14 29.025 ;
     RECT  26.352 28.755 43.632 29.025 ;
     RECT  47.844 28.755 64.044 29.025 ;
     RECT  240.948 28.755 265.68 29.025 ;
     RECT  2.16 29.295 22.14 29.565 ;
     RECT  26.352 29.295 43.632 29.565 ;
     RECT  47.844 29.295 64.044 29.565 ;
     RECT  240.948 29.295 265.68 29.565 ;
     RECT  2.16 29.835 22.14 30.105 ;
     RECT  26.352 29.835 43.632 30.105 ;
     RECT  47.844 29.835 64.044 30.105 ;
     RECT  240.948 29.835 265.68 30.105 ;
     RECT  2.16 30.375 22.14 30.645 ;
     RECT  26.352 30.375 43.632 30.645 ;
     RECT  47.844 30.375 64.044 30.645 ;
     RECT  240.948 30.375 265.68 30.645 ;
     RECT  2.16 30.915 22.14 31.185 ;
     RECT  26.352 30.915 43.632 31.185 ;
     RECT  47.844 30.915 64.044 31.185 ;
     RECT  240.948 30.915 265.68 31.185 ;
     RECT  2.16 31.455 22.14 31.725 ;
     RECT  26.352 31.455 43.632 31.725 ;
     RECT  47.844 31.455 64.044 31.725 ;
     RECT  240.948 31.455 265.68 31.725 ;
     RECT  2.16 31.995 22.14 32.265 ;
     RECT  26.352 31.995 43.632 32.265 ;
     RECT  47.844 31.995 64.044 32.265 ;
     RECT  240.948 31.995 265.68 32.265 ;
     RECT  2.16 32.535 22.14 32.805 ;
     RECT  26.352 32.535 43.632 32.805 ;
     RECT  47.844 32.535 64.044 32.805 ;
     RECT  240.948 32.535 265.68 32.805 ;
     RECT  2.16 33.075 22.14 33.345 ;
     RECT  26.352 33.075 43.632 33.345 ;
     RECT  47.844 33.075 64.044 33.345 ;
     RECT  240.948 33.075 265.68 33.345 ;
     RECT  2.16 33.615 22.14 33.885 ;
     RECT  26.352 33.615 43.632 33.885 ;
     RECT  47.844 33.615 64.044 33.885 ;
     RECT  240.948 33.615 265.68 33.885 ;
     RECT  2.16 34.155 22.14 34.425 ;
     RECT  26.352 34.155 43.632 34.425 ;
     RECT  47.844 34.155 64.044 34.425 ;
     RECT  240.948 34.155 265.68 34.425 ;
     RECT  2.16 34.695 22.14 34.965 ;
     RECT  26.352 34.695 43.632 34.965 ;
     RECT  47.844 34.695 64.044 34.965 ;
     RECT  240.948 34.695 265.68 34.965 ;
     RECT  2.16 35.235 22.14 35.505 ;
     RECT  26.352 35.235 43.632 35.505 ;
     RECT  47.844 35.235 64.044 35.505 ;
     RECT  240.948 35.235 265.68 35.505 ;
     RECT  2.16 35.775 22.14 36.045 ;
     RECT  26.352 35.775 43.632 36.045 ;
     RECT  47.844 35.775 64.044 36.045 ;
     RECT  240.948 35.775 265.68 36.045 ;
     RECT  2.16 36.315 22.14 36.585 ;
     RECT  26.352 36.315 43.632 36.585 ;
     RECT  47.844 36.315 64.044 36.585 ;
     RECT  240.948 36.315 265.68 36.585 ;
     RECT  2.16 36.855 22.14 37.125 ;
     RECT  26.352 36.855 43.632 37.125 ;
     RECT  47.844 36.855 64.044 37.125 ;
     RECT  240.948 36.855 265.68 37.125 ;
     RECT  2.16 37.395 22.14 37.665 ;
     RECT  26.352 37.395 43.632 37.665 ;
     RECT  47.844 37.395 64.044 37.665 ;
     RECT  240.948 37.395 265.68 37.665 ;
     RECT  2.16 37.935 22.14 38.205 ;
     RECT  26.352 37.935 43.632 38.205 ;
     RECT  47.844 37.935 64.044 38.205 ;
     RECT  240.948 37.935 265.68 38.205 ;
     RECT  2.16 38.475 22.14 38.745 ;
     RECT  26.352 38.475 43.632 38.745 ;
     RECT  47.844 38.475 64.044 38.745 ;
     RECT  240.948 38.475 265.68 38.745 ;
     RECT  2.16 39.015 22.14 39.285 ;
     RECT  26.352 39.015 43.632 39.285 ;
     RECT  47.844 39.015 64.044 39.285 ;
     RECT  240.948 39.015 265.68 39.285 ;
     RECT  2.16 39.555 22.14 39.825 ;
     RECT  26.352 39.555 43.632 39.825 ;
     RECT  47.844 39.555 64.044 39.825 ;
     RECT  240.948 39.555 265.68 39.825 ;
     RECT  2.16 40.095 22.14 40.365 ;
     RECT  26.352 40.095 43.632 40.365 ;
     RECT  47.844 40.095 64.044 40.365 ;
     RECT  240.948 40.095 265.68 40.365 ;
     RECT  2.16 40.635 22.14 40.905 ;
     RECT  26.352 40.635 43.632 40.905 ;
     RECT  47.844 40.635 64.044 40.905 ;
     RECT  240.948 40.635 265.68 40.905 ;
     RECT  2.16 41.175 22.14 41.445 ;
     RECT  26.352 41.175 43.632 41.445 ;
     RECT  47.844 41.175 64.044 41.445 ;
     RECT  240.948 41.175 265.68 41.445 ;
     RECT  2.16 41.715 22.14 41.985 ;
     RECT  26.352 41.715 43.632 41.985 ;
     RECT  47.844 41.715 64.044 41.985 ;
     RECT  240.948 41.715 265.68 41.985 ;
     RECT  2.16 42.255 22.14 42.525 ;
     RECT  26.352 42.255 43.632 42.525 ;
     RECT  47.844 42.255 64.044 42.525 ;
     RECT  240.948 42.255 265.68 42.525 ;
     RECT  2.16 42.795 22.14 43.065 ;
     RECT  26.352 42.795 43.632 43.065 ;
     RECT  47.844 42.795 64.044 43.065 ;
     RECT  240.948 42.795 265.68 43.065 ;
     RECT  2.16 43.335 22.14 43.605 ;
     RECT  26.352 43.335 43.632 43.605 ;
     RECT  47.844 43.335 64.044 43.605 ;
     RECT  240.948 43.335 265.68 43.605 ;
     RECT  2.16 43.875 22.14 44.145 ;
     RECT  26.352 43.875 43.632 44.145 ;
     RECT  47.844 43.875 64.044 44.145 ;
     RECT  240.948 43.875 265.68 44.145 ;
     RECT  2.16 44.415 22.14 44.685 ;
     RECT  26.352 44.415 43.632 44.685 ;
     RECT  47.844 44.415 64.044 44.685 ;
     RECT  240.948 44.415 265.68 44.685 ;
     RECT  2.16 44.955 22.14 45.225 ;
     RECT  26.352 44.955 43.632 45.225 ;
     RECT  47.844 44.955 64.044 45.225 ;
     RECT  240.948 44.955 265.68 45.225 ;
     RECT  2.16 45.495 22.14 45.765 ;
     RECT  47.844 45.495 64.044 45.765 ;
     RECT  240.948 45.495 265.68 45.765 ;
     RECT  2.16 46.035 22.14 46.305 ;
     RECT  47.844 46.035 64.044 46.305 ;
     RECT  240.948 46.035 265.68 46.305 ;
     RECT  2.16 46.575 22.14 46.845 ;
     RECT  47.844 46.575 64.044 46.845 ;
     RECT  240.948 46.575 265.68 46.845 ;
     RECT  2.16 47.115 22.14 47.385 ;
     RECT  47.844 47.115 64.044 47.385 ;
     RECT  240.948 47.115 265.68 47.385 ;
     RECT  2.16 47.655 22.14 47.925 ;
     RECT  47.844 47.655 64.044 47.925 ;
     RECT  240.948 47.655 265.68 47.925 ;
     RECT  2.16 48.195 22.14 48.465 ;
     RECT  47.844 48.195 64.044 48.465 ;
     RECT  240.948 48.195 265.68 48.465 ;
     RECT  2.16 48.735 22.14 49.005 ;
     RECT  47.844 48.735 64.044 49.005 ;
     RECT  240.948 48.735 265.68 49.005 ;
     RECT  2.16 49.275 22.14 49.545 ;
     RECT  47.844 49.275 64.044 49.545 ;
     RECT  240.948 49.275 265.68 49.545 ;
     RECT  2.16 49.815 64.044 50.085 ;
     RECT  240.948 49.815 265.68 50.085 ;
     RECT  2.16 50.355 64.044 50.625 ;
     RECT  240.948 50.355 265.68 50.625 ;
     RECT  2.16 50.895 64.044 51.165 ;
     RECT  240.948 50.895 265.68 51.165 ;
     RECT  2.16 51.435 64.044 51.705 ;
     RECT  240.948 51.435 265.68 51.705 ;
     RECT  2.16 51.975 64.044 52.245 ;
     RECT  240.948 51.975 265.68 52.245 ;
     RECT  2.16 52.515 64.044 52.785 ;
     RECT  240.948 52.515 265.68 52.785 ;
     RECT  2.16 53.055 64.044 53.325 ;
     RECT  240.948 53.055 265.68 53.325 ;
     RECT  2.16 53.595 64.044 53.865 ;
     RECT  240.948 53.595 265.68 53.865 ;
     RECT  2.16 54.135 64.044 54.405 ;
     RECT  240.948 54.135 265.68 54.405 ;
     RECT  2.16 54.675 64.044 54.945 ;
     RECT  240.948 54.675 265.68 54.945 ;
     RECT  2.16 55.215 64.044 55.485 ;
     RECT  240.948 55.215 265.68 55.485 ;
     RECT  2.16 55.755 64.044 56.025 ;
     RECT  240.948 55.755 265.68 56.025 ;
     RECT  2.16 56.295 64.044 56.565 ;
     RECT  240.948 56.295 265.68 56.565 ;
     RECT  2.16 56.835 64.044 57.105 ;
     RECT  240.948 56.835 265.68 57.105 ;
     RECT  2.16 57.375 64.044 57.645 ;
     RECT  240.948 57.375 265.68 57.645 ;
     RECT  2.16 57.915 64.044 58.185 ;
     RECT  240.948 57.915 265.68 58.185 ;
     RECT  2.16 58.455 64.044 58.725 ;
     RECT  240.948 58.455 265.68 58.725 ;
     RECT  2.16 58.995 64.044 59.265 ;
     RECT  240.948 58.995 265.68 59.265 ;
     RECT  2.16 59.535 64.044 59.805 ;
     RECT  240.948 59.535 265.68 59.805 ;
     RECT  2.16 60.075 64.044 60.345 ;
     RECT  240.948 60.075 265.68 60.345 ;
     RECT  2.16 60.615 64.044 60.885 ;
     RECT  240.948 60.615 265.68 60.885 ;
     RECT  2.16 61.155 64.044 61.425 ;
     RECT  240.948 61.155 265.68 61.425 ;
     RECT  2.16 61.695 64.044 61.965 ;
     RECT  240.948 61.695 265.68 61.965 ;
     RECT  2.16 62.235 64.044 62.505 ;
     RECT  240.948 62.235 265.68 62.505 ;
     RECT  2.16 62.775 64.044 63.045 ;
     RECT  240.948 62.775 265.68 63.045 ;
     RECT  2.16 63.315 64.044 63.585 ;
     RECT  240.948 63.315 265.68 63.585 ;
     RECT  2.16 63.855 64.044 64.125 ;
     RECT  240.948 63.855 265.68 64.125 ;
     RECT  2.16 64.395 64.044 64.665 ;
     RECT  240.948 64.395 265.68 64.665 ;
     RECT  2.16 64.935 64.044 65.205 ;
     RECT  240.948 64.935 265.68 65.205 ;
     RECT  2.16 65.475 64.044 65.745 ;
     RECT  240.948 65.475 265.68 65.745 ;
     RECT  2.16 66.015 64.044 66.285 ;
     RECT  240.948 66.015 265.68 66.285 ;
     RECT  2.16 66.555 64.044 66.825 ;
     RECT  240.948 66.555 265.68 66.825 ;
     RECT  2.16 67.095 64.044 67.365 ;
     RECT  240.948 67.095 265.68 67.365 ;
     RECT  2.16 67.635 64.044 67.905 ;
     RECT  240.948 67.635 265.68 67.905 ;
     RECT  2.16 68.175 64.044 68.445 ;
     RECT  240.948 68.175 265.68 68.445 ;
     RECT  2.16 68.715 64.044 68.985 ;
     RECT  240.948 68.715 265.68 68.985 ;
     RECT  2.16 69.255 64.044 69.525 ;
     RECT  240.948 69.255 265.68 69.525 ;
     RECT  2.16 69.795 64.044 70.065 ;
     RECT  240.948 69.795 265.68 70.065 ;
     RECT  2.16 70.335 64.044 70.605 ;
     RECT  240.948 70.335 265.68 70.605 ;
     RECT  2.16 70.875 64.044 71.145 ;
     RECT  240.948 70.875 265.68 71.145 ;
     RECT  2.16 71.415 64.044 71.685 ;
     RECT  240.948 71.415 265.68 71.685 ;
     RECT  2.16 71.955 64.044 72.225 ;
     RECT  240.948 71.955 265.68 72.225 ;
     RECT  2.16 72.495 64.044 72.765 ;
     RECT  240.948 72.495 265.68 72.765 ;
     RECT  2.16 73.035 64.044 73.305 ;
     RECT  240.948 73.035 265.68 73.305 ;
     RECT  2.16 73.575 64.044 73.845 ;
     RECT  240.948 73.575 265.68 73.845 ;
     RECT  2.16 74.115 64.044 74.385 ;
     RECT  240.948 74.115 265.68 74.385 ;
     RECT  2.16 74.655 64.044 74.925 ;
     RECT  240.948 74.655 265.68 74.925 ;
     RECT  2.16 75.195 64.044 75.465 ;
     RECT  240.948 75.195 265.68 75.465 ;
     RECT  2.16 75.735 64.044 76.005 ;
     RECT  240.948 75.735 265.68 76.005 ;
     RECT  2.16 76.275 64.044 76.545 ;
     RECT  240.948 76.275 265.68 76.545 ;
     RECT  2.16 76.815 64.044 77.085 ;
     RECT  240.948 76.815 265.68 77.085 ;
     RECT  2.16 77.355 64.044 77.625 ;
     RECT  240.948 77.355 265.68 77.625 ;
     RECT  2.16 77.895 64.044 78.165 ;
     RECT  240.948 77.895 265.68 78.165 ;
     RECT  2.16 78.435 64.044 78.705 ;
     RECT  240.948 78.435 265.68 78.705 ;
     RECT  2.16 78.975 64.044 79.245 ;
     RECT  240.948 78.975 265.68 79.245 ;
     RECT  2.16 79.515 64.044 79.785 ;
     RECT  240.948 79.515 265.68 79.785 ;
     RECT  2.16 80.055 64.044 80.325 ;
     RECT  240.948 80.055 265.68 80.325 ;
     RECT  2.16 80.595 64.044 80.865 ;
     RECT  240.948 80.595 265.68 80.865 ;
     RECT  2.16 81.135 64.044 81.405 ;
     RECT  240.948 81.135 265.68 81.405 ;
     RECT  2.16 81.675 64.044 81.945 ;
     RECT  240.948 81.675 265.68 81.945 ;
     RECT  2.16 82.215 64.044 82.485 ;
     RECT  240.948 82.215 265.68 82.485 ;
     RECT  2.16 82.755 64.044 83.025 ;
     RECT  240.948 82.755 265.68 83.025 ;
     RECT  2.16 83.295 64.044 83.565 ;
     RECT  240.948 83.295 265.68 83.565 ;
     RECT  2.16 83.835 64.044 84.105 ;
     RECT  240.948 83.835 265.68 84.105 ;
     RECT  2.16 84.375 64.044 84.645 ;
     RECT  240.948 84.375 265.68 84.645 ;
     RECT  2.16 84.915 64.044 85.185 ;
     RECT  240.948 84.915 265.68 85.185 ;
     RECT  2.16 85.455 64.044 85.725 ;
     RECT  240.948 85.455 265.68 85.725 ;
     RECT  2.16 85.995 64.044 86.265 ;
     RECT  240.948 85.995 265.68 86.265 ;
     RECT  2.16 86.535 64.044 86.805 ;
     RECT  240.948 86.535 265.68 86.805 ;
     RECT  2.16 87.075 64.044 87.345 ;
     RECT  240.948 87.075 265.68 87.345 ;
     RECT  2.16 87.615 64.044 87.885 ;
     RECT  240.948 87.615 265.68 87.885 ;
     RECT  2.16 88.155 64.044 88.425 ;
     RECT  240.948 88.155 265.68 88.425 ;
     RECT  2.16 88.695 64.044 88.965 ;
     RECT  240.948 88.695 265.68 88.965 ;
     RECT  2.16 89.235 64.044 89.505 ;
     RECT  240.948 89.235 265.68 89.505 ;
     RECT  2.16 89.775 64.044 90.045 ;
     RECT  240.948 89.775 265.68 90.045 ;
     RECT  2.16 90.315 64.044 90.585 ;
     RECT  240.948 90.315 265.68 90.585 ;
     RECT  2.16 90.855 64.044 91.125 ;
     RECT  240.948 90.855 265.68 91.125 ;
     RECT  2.16 91.395 64.044 91.665 ;
     RECT  240.948 91.395 265.68 91.665 ;
     RECT  2.16 91.935 64.044 92.205 ;
     RECT  240.948 91.935 265.68 92.205 ;
     RECT  2.16 92.475 64.044 92.745 ;
     RECT  240.948 92.475 265.68 92.745 ;
     RECT  2.16 93.015 64.044 93.285 ;
     RECT  240.948 93.015 265.68 93.285 ;
     RECT  2.16 93.555 64.044 93.825 ;
     RECT  240.948 93.555 265.68 93.825 ;
     RECT  2.16 94.095 64.044 94.365 ;
     RECT  240.948 94.095 265.68 94.365 ;
     RECT  2.16 94.635 64.044 94.905 ;
     RECT  240.948 94.635 265.68 94.905 ;
     RECT  2.16 95.175 64.044 95.445 ;
     RECT  240.948 95.175 265.68 95.445 ;
     RECT  2.16 95.715 64.044 95.985 ;
     RECT  240.948 95.715 265.68 95.985 ;
     RECT  2.16 96.255 64.044 96.525 ;
     RECT  240.948 96.255 265.68 96.525 ;
     RECT  2.16 96.795 64.044 97.065 ;
     RECT  240.948 96.795 265.68 97.065 ;
     RECT  2.16 97.335 64.044 97.605 ;
     RECT  240.948 97.335 265.68 97.605 ;
     RECT  2.16 97.875 64.044 98.145 ;
     RECT  240.948 97.875 265.68 98.145 ;
     RECT  2.16 98.415 64.044 98.685 ;
     RECT  240.948 98.415 265.68 98.685 ;
     RECT  2.16 98.955 64.044 99.225 ;
     RECT  240.948 98.955 265.68 99.225 ;
     RECT  2.16 99.495 64.044 99.765 ;
     RECT  240.948 99.495 265.68 99.765 ;
     RECT  2.16 100.035 64.044 100.305 ;
     RECT  240.948 100.035 265.68 100.305 ;
     RECT  2.16 100.575 64.044 100.845 ;
     RECT  240.948 100.575 265.68 100.845 ;
     RECT  2.16 101.115 64.044 101.385 ;
     RECT  240.948 101.115 265.68 101.385 ;
     RECT  2.16 101.655 64.044 101.925 ;
     RECT  240.948 101.655 265.68 101.925 ;
     RECT  2.16 102.195 64.044 102.465 ;
     RECT  240.948 102.195 265.68 102.465 ;
     RECT  2.16 102.735 64.044 103.005 ;
     RECT  240.948 102.735 265.68 103.005 ;
     RECT  2.16 103.275 64.044 103.545 ;
     RECT  240.948 103.275 265.68 103.545 ;
     RECT  2.16 103.815 64.044 104.085 ;
     RECT  240.948 103.815 265.68 104.085 ;
     RECT  2.16 104.355 64.044 104.625 ;
     RECT  240.948 104.355 265.68 104.625 ;
     RECT  2.16 104.895 64.044 105.165 ;
     RECT  240.948 104.895 265.68 105.165 ;
     RECT  2.16 105.435 64.044 105.705 ;
     RECT  240.948 105.435 265.68 105.705 ;
     RECT  2.16 105.975 64.044 106.245 ;
     RECT  240.948 105.975 265.68 106.245 ;
     RECT  2.16 106.515 64.044 106.785 ;
     RECT  240.948 106.515 265.68 106.785 ;
     RECT  2.16 107.055 64.044 107.325 ;
     RECT  240.948 107.055 265.68 107.325 ;
     RECT  2.16 107.595 64.044 107.865 ;
     RECT  240.948 107.595 265.68 107.865 ;
     RECT  2.16 108.135 64.044 108.405 ;
     RECT  240.948 108.135 265.68 108.405 ;
     RECT  2.16 108.675 64.044 108.945 ;
     RECT  240.948 108.675 265.68 108.945 ;
     RECT  2.16 109.215 64.044 109.485 ;
     RECT  240.948 109.215 265.68 109.485 ;
     RECT  2.16 109.755 64.044 110.025 ;
     RECT  240.948 109.755 265.68 110.025 ;
     RECT  2.16 110.295 64.044 110.565 ;
     RECT  240.948 110.295 265.68 110.565 ;
     RECT  2.16 110.835 64.044 111.105 ;
     RECT  240.948 110.835 265.68 111.105 ;
     RECT  2.16 111.375 64.044 111.645 ;
     RECT  240.948 111.375 265.68 111.645 ;
     RECT  2.16 111.915 64.044 112.185 ;
     RECT  240.948 111.915 265.68 112.185 ;
     RECT  2.16 112.455 64.044 112.725 ;
     RECT  240.948 112.455 265.68 112.725 ;
     RECT  2.16 112.995 64.044 113.265 ;
     RECT  240.948 112.995 265.68 113.265 ;
     RECT  2.16 113.535 64.044 113.805 ;
     RECT  240.948 113.535 265.68 113.805 ;
     RECT  2.16 114.075 64.044 114.345 ;
     RECT  240.948 114.075 265.68 114.345 ;
     RECT  2.16 114.615 64.044 114.885 ;
     RECT  240.948 114.615 265.68 114.885 ;
     RECT  2.16 115.155 64.044 115.425 ;
     RECT  240.948 115.155 265.68 115.425 ;
     RECT  2.16 115.695 64.044 115.965 ;
     RECT  240.948 115.695 265.68 115.965 ;
     RECT  2.16 116.235 64.044 116.505 ;
     RECT  240.948 116.235 265.68 116.505 ;
     RECT  2.16 116.775 64.044 117.045 ;
     RECT  240.948 116.775 265.68 117.045 ;
     RECT  2.16 117.315 64.044 117.585 ;
     RECT  240.948 117.315 265.68 117.585 ;
     RECT  2.16 117.855 64.044 118.125 ;
     RECT  240.948 117.855 265.68 118.125 ;
     RECT  2.16 118.395 64.044 118.665 ;
     RECT  240.948 118.395 265.68 118.665 ;
     RECT  2.16 118.935 64.044 119.205 ;
     RECT  240.948 118.935 265.68 119.205 ;
     RECT  2.16 119.475 64.044 119.745 ;
     RECT  240.948 119.475 265.68 119.745 ;
     RECT  2.16 120.015 64.044 120.285 ;
     RECT  240.948 120.015 265.68 120.285 ;
     RECT  2.16 120.555 64.044 120.825 ;
     RECT  240.948 120.555 265.68 120.825 ;
     RECT  2.16 121.095 64.044 121.365 ;
     RECT  240.948 121.095 265.68 121.365 ;
     RECT  2.16 121.635 64.044 121.905 ;
     RECT  240.948 121.635 265.68 121.905 ;
     RECT  2.16 122.175 64.044 122.445 ;
     RECT  240.948 122.175 265.68 122.445 ;
     RECT  2.16 122.715 64.044 122.985 ;
     RECT  240.948 122.715 265.68 122.985 ;
     RECT  2.16 123.255 64.044 123.525 ;
     RECT  240.948 123.255 265.68 123.525 ;
     RECT  2.16 123.795 64.044 124.065 ;
     RECT  240.948 123.795 265.68 124.065 ;
     RECT  2.16 124.335 64.044 124.605 ;
     RECT  240.948 124.335 265.68 124.605 ;
     RECT  2.16 124.875 64.044 125.145 ;
     RECT  240.948 124.875 265.68 125.145 ;
     RECT  2.16 125.415 64.044 125.685 ;
     RECT  240.948 125.415 265.68 125.685 ;
     RECT  2.16 125.955 64.044 126.225 ;
     RECT  240.948 125.955 265.68 126.225 ;
     RECT  2.16 126.495 64.044 126.765 ;
     RECT  240.948 126.495 265.68 126.765 ;
     RECT  2.16 127.035 64.044 127.305 ;
     RECT  240.948 127.035 265.68 127.305 ;
     RECT  2.16 127.575 64.044 127.845 ;
     RECT  240.948 127.575 265.68 127.845 ;
     RECT  2.16 128.115 64.044 128.385 ;
     RECT  240.948 128.115 265.68 128.385 ;
     RECT  2.16 128.655 64.044 128.925 ;
     RECT  240.948 128.655 265.68 128.925 ;
     RECT  2.16 129.195 64.044 129.465 ;
     RECT  240.948 129.195 265.68 129.465 ;
     RECT  2.16 129.735 64.044 130.005 ;
     RECT  240.948 129.735 265.68 130.005 ;
     RECT  2.16 130.275 64.044 130.545 ;
     RECT  240.948 130.275 265.68 130.545 ;
     RECT  2.16 130.815 64.044 131.085 ;
     RECT  240.948 130.815 265.68 131.085 ;
     RECT  2.16 131.355 64.044 131.625 ;
     RECT  240.948 131.355 265.68 131.625 ;
     RECT  2.16 131.895 64.044 132.165 ;
     RECT  240.948 131.895 265.68 132.165 ;
     RECT  2.16 132.435 64.044 132.705 ;
     RECT  240.948 132.435 265.68 132.705 ;
     RECT  2.16 132.975 64.044 133.245 ;
     RECT  240.948 132.975 265.68 133.245 ;
     RECT  2.16 133.515 64.044 133.785 ;
     RECT  240.948 133.515 265.68 133.785 ;
     RECT  2.16 134.055 64.044 134.325 ;
     RECT  240.948 134.055 265.68 134.325 ;
     RECT  2.16 134.595 64.044 134.865 ;
     RECT  240.948 134.595 265.68 134.865 ;
     RECT  2.16 135.135 64.044 135.405 ;
     RECT  240.948 135.135 265.68 135.405 ;
     RECT  2.16 135.675 64.044 135.945 ;
     RECT  240.948 135.675 265.68 135.945 ;
     RECT  2.16 136.215 64.044 136.485 ;
     RECT  240.948 136.215 265.68 136.485 ;
     RECT  2.16 136.755 64.044 137.025 ;
     RECT  240.948 136.755 265.68 137.025 ;
     RECT  2.16 137.295 64.044 137.565 ;
     RECT  240.948 137.295 265.68 137.565 ;
     RECT  2.16 137.835 64.044 138.105 ;
     RECT  240.948 137.835 265.68 138.105 ;
     RECT  2.16 138.375 64.044 138.645 ;
     RECT  240.948 138.375 265.68 138.645 ;
     RECT  2.16 138.915 64.044 139.185 ;
     RECT  240.948 138.915 265.68 139.185 ;
     RECT  2.16 139.455 64.044 139.725 ;
     RECT  240.948 139.455 265.68 139.725 ;
     RECT  2.16 139.995 64.044 140.265 ;
     RECT  240.948 139.995 265.68 140.265 ;
     RECT  2.16 140.535 64.044 140.805 ;
     RECT  240.948 140.535 265.68 140.805 ;
     RECT  2.16 141.075 64.044 141.345 ;
     RECT  240.948 141.075 265.68 141.345 ;
     RECT  2.16 141.615 64.044 141.885 ;
     RECT  240.948 141.615 265.68 141.885 ;
     RECT  2.16 142.155 64.044 142.425 ;
     RECT  240.948 142.155 265.68 142.425 ;
     RECT  2.16 142.695 64.044 142.965 ;
     RECT  240.948 142.695 265.68 142.965 ;
     RECT  2.16 143.235 64.044 143.505 ;
     RECT  240.948 143.235 265.68 143.505 ;
     RECT  2.16 143.775 64.044 144.045 ;
     RECT  240.948 143.775 265.68 144.045 ;
     RECT  2.16 144.315 64.044 144.585 ;
     RECT  240.948 144.315 265.68 144.585 ;
     RECT  2.16 144.855 64.044 145.125 ;
     RECT  240.948 144.855 265.68 145.125 ;
     RECT  2.16 145.395 64.044 145.665 ;
     RECT  240.948 145.395 265.68 145.665 ;
     RECT  2.16 145.935 64.044 146.205 ;
     RECT  240.948 145.935 265.68 146.205 ;
     RECT  2.16 146.475 64.044 146.745 ;
     RECT  240.948 146.475 265.68 146.745 ;
     RECT  2.16 147.015 64.044 147.285 ;
     RECT  240.948 147.015 265.68 147.285 ;
     RECT  2.16 147.555 64.044 147.825 ;
     RECT  240.948 147.555 265.68 147.825 ;
     RECT  2.16 148.095 64.044 148.365 ;
     RECT  240.948 148.095 265.68 148.365 ;
     RECT  2.16 148.635 64.044 148.905 ;
     RECT  240.948 148.635 265.68 148.905 ;
     RECT  2.16 149.175 64.044 149.445 ;
     RECT  240.948 149.175 265.68 149.445 ;
     RECT  2.16 149.715 64.044 149.985 ;
     RECT  240.948 149.715 265.68 149.985 ;
     RECT  2.16 150.255 64.044 150.525 ;
     RECT  240.948 150.255 265.68 150.525 ;
     RECT  2.16 150.795 64.044 151.065 ;
     RECT  240.948 150.795 265.68 151.065 ;
     RECT  2.16 151.335 64.044 151.605 ;
     RECT  240.948 151.335 265.68 151.605 ;
     RECT  2.16 151.875 64.044 152.145 ;
     RECT  240.948 151.875 265.68 152.145 ;
     RECT  2.16 152.415 64.044 152.685 ;
     RECT  240.948 152.415 265.68 152.685 ;
     RECT  2.16 152.955 64.044 153.225 ;
     RECT  240.948 152.955 265.68 153.225 ;
     RECT  2.16 153.495 64.044 153.765 ;
     RECT  240.948 153.495 265.68 153.765 ;
     RECT  2.16 154.035 64.044 154.305 ;
     RECT  240.948 154.035 265.68 154.305 ;
     RECT  2.16 154.575 64.044 154.845 ;
     RECT  240.948 154.575 265.68 154.845 ;
     RECT  2.16 155.115 64.044 155.385 ;
     RECT  240.948 155.115 265.68 155.385 ;
     RECT  2.16 155.655 64.044 155.925 ;
     RECT  240.948 155.655 265.68 155.925 ;
     RECT  2.16 156.195 64.044 156.465 ;
     RECT  240.948 156.195 265.68 156.465 ;
     RECT  2.16 156.735 64.044 157.005 ;
     RECT  240.948 156.735 265.68 157.005 ;
     RECT  2.16 157.275 64.044 157.545 ;
     RECT  240.948 157.275 265.68 157.545 ;
     RECT  2.16 157.815 64.044 158.085 ;
     RECT  240.948 157.815 265.68 158.085 ;
     RECT  2.16 158.355 64.044 158.625 ;
     RECT  240.948 158.355 265.68 158.625 ;
     RECT  2.16 158.895 64.044 159.165 ;
     RECT  240.948 158.895 265.68 159.165 ;
     RECT  2.16 159.435 64.044 159.705 ;
     RECT  240.948 159.435 265.68 159.705 ;
     RECT  2.16 159.975 64.044 160.245 ;
     RECT  240.948 159.975 265.68 160.245 ;
     RECT  2.16 160.515 64.044 160.785 ;
     RECT  240.948 160.515 265.68 160.785 ;
     RECT  2.16 161.055 64.044 161.325 ;
     RECT  240.948 161.055 265.68 161.325 ;
     RECT  2.16 161.595 64.044 161.865 ;
     RECT  240.948 161.595 265.68 161.865 ;
     RECT  2.16 162.135 64.044 162.405 ;
     RECT  240.948 162.135 265.68 162.405 ;
     RECT  2.16 162.675 64.044 162.945 ;
     RECT  240.948 162.675 265.68 162.945 ;
     RECT  2.16 163.215 64.044 163.485 ;
     RECT  240.948 163.215 265.68 163.485 ;
     RECT  2.16 163.755 64.044 164.025 ;
     RECT  240.948 163.755 265.68 164.025 ;
     RECT  2.16 164.295 64.044 164.565 ;
     RECT  240.948 164.295 265.68 164.565 ;
     RECT  2.16 164.835 64.044 165.105 ;
     RECT  240.948 164.835 265.68 165.105 ;
     RECT  2.16 165.375 64.044 165.645 ;
     RECT  240.948 165.375 265.68 165.645 ;
     RECT  2.16 165.915 64.044 166.185 ;
     RECT  240.948 165.915 265.68 166.185 ;
     RECT  2.16 166.455 64.044 166.725 ;
     RECT  240.948 166.455 265.68 166.725 ;
     RECT  2.16 166.995 64.044 167.265 ;
     RECT  240.948 166.995 265.68 167.265 ;
     RECT  2.16 167.535 64.044 167.805 ;
     RECT  240.948 167.535 265.68 167.805 ;
     RECT  2.16 168.075 64.044 168.345 ;
     RECT  240.948 168.075 265.68 168.345 ;
     RECT  2.16 168.615 64.044 168.885 ;
     RECT  240.948 168.615 265.68 168.885 ;
     RECT  2.16 169.155 64.044 169.425 ;
     RECT  240.948 169.155 265.68 169.425 ;
     RECT  2.16 169.695 64.044 169.965 ;
     RECT  240.948 169.695 265.68 169.965 ;
     RECT  2.16 170.235 64.044 170.505 ;
     RECT  240.948 170.235 265.68 170.505 ;
     RECT  2.16 170.775 64.044 171.045 ;
     RECT  240.948 170.775 265.68 171.045 ;
     RECT  2.16 171.315 64.044 171.585 ;
     RECT  240.948 171.315 265.68 171.585 ;
     RECT  2.16 171.855 64.044 172.125 ;
     RECT  240.948 171.855 265.68 172.125 ;
     RECT  2.16 172.395 64.044 172.665 ;
     RECT  240.948 172.395 265.68 172.665 ;
     RECT  2.16 172.935 64.044 173.205 ;
     RECT  240.948 172.935 265.68 173.205 ;
     RECT  2.16 173.475 64.044 173.745 ;
     RECT  240.948 173.475 265.68 173.745 ;
     RECT  2.16 174.015 64.044 174.285 ;
     RECT  240.948 174.015 265.68 174.285 ;
     RECT  2.16 174.555 64.044 174.825 ;
     RECT  240.948 174.555 265.68 174.825 ;
     RECT  2.16 175.095 64.044 175.365 ;
     RECT  240.948 175.095 265.68 175.365 ;
     RECT  2.16 175.635 64.044 175.905 ;
     RECT  240.948 175.635 265.68 175.905 ;
     RECT  2.16 176.175 64.044 176.445 ;
     RECT  240.948 176.175 265.68 176.445 ;
     RECT  2.16 176.715 64.044 176.985 ;
     RECT  240.948 176.715 265.68 176.985 ;
     RECT  2.16 177.255 64.044 177.525 ;
     RECT  240.948 177.255 265.68 177.525 ;
     RECT  2.16 177.795 64.044 178.065 ;
     RECT  240.948 177.795 265.68 178.065 ;
     RECT  2.16 178.335 64.044 178.605 ;
     RECT  240.948 178.335 265.68 178.605 ;
     RECT  2.16 178.875 64.044 179.145 ;
     RECT  240.948 178.875 265.68 179.145 ;
     RECT  2.16 179.415 64.044 179.685 ;
     RECT  240.948 179.415 265.68 179.685 ;
     RECT  2.16 179.955 64.044 180.225 ;
     RECT  240.948 179.955 265.68 180.225 ;
     RECT  2.16 180.495 64.044 180.765 ;
     RECT  240.948 180.495 265.68 180.765 ;
     RECT  2.16 181.035 64.044 181.305 ;
     RECT  240.948 181.035 265.68 181.305 ;
     RECT  2.16 181.575 64.044 181.845 ;
     RECT  240.948 181.575 265.68 181.845 ;
     RECT  2.16 182.115 64.044 182.385 ;
     RECT  240.948 182.115 265.68 182.385 ;
     RECT  2.16 182.655 64.044 182.925 ;
     RECT  240.948 182.655 265.68 182.925 ;
     RECT  2.16 183.195 64.044 183.465 ;
     RECT  240.948 183.195 265.68 183.465 ;
     RECT  2.16 183.735 64.044 184.005 ;
     RECT  240.948 183.735 265.68 184.005 ;
     RECT  2.16 184.275 64.044 184.545 ;
     RECT  240.948 184.275 265.68 184.545 ;
     RECT  2.16 184.815 64.044 185.085 ;
     RECT  240.948 184.815 265.68 185.085 ;
     RECT  2.16 185.355 64.044 185.625 ;
     RECT  240.948 185.355 265.68 185.625 ;
     RECT  2.16 185.895 64.044 186.165 ;
     RECT  240.948 185.895 265.68 186.165 ;
     RECT  2.16 186.435 64.044 186.705 ;
     RECT  240.948 186.435 265.68 186.705 ;
     RECT  2.16 186.975 64.044 187.245 ;
     RECT  240.948 186.975 265.68 187.245 ;
     RECT  2.16 187.515 64.044 187.785 ;
     RECT  240.948 187.515 265.68 187.785 ;
     RECT  2.16 188.055 64.044 188.325 ;
     RECT  240.948 188.055 265.68 188.325 ;
     RECT  2.16 188.595 64.044 188.865 ;
     RECT  240.948 188.595 265.68 188.865 ;
     RECT  2.16 189.135 64.044 189.405 ;
     RECT  240.948 189.135 265.68 189.405 ;
     RECT  2.16 189.675 64.044 189.945 ;
     RECT  240.948 189.675 265.68 189.945 ;
     RECT  2.16 190.215 64.044 190.485 ;
     RECT  240.948 190.215 265.68 190.485 ;
     RECT  2.16 190.755 64.044 191.025 ;
     RECT  240.948 190.755 265.68 191.025 ;
     RECT  2.16 191.295 64.044 191.565 ;
     RECT  240.948 191.295 265.68 191.565 ;
     RECT  2.16 191.835 64.044 192.105 ;
     RECT  240.948 191.835 265.68 192.105 ;
     RECT  2.16 192.375 64.044 192.645 ;
     RECT  240.948 192.375 265.68 192.645 ;
     RECT  2.16 192.915 64.044 193.185 ;
     RECT  240.948 192.915 265.68 193.185 ;
     RECT  2.16 193.455 64.044 193.725 ;
     RECT  240.948 193.455 265.68 193.725 ;
     RECT  2.16 193.995 64.044 194.265 ;
     RECT  240.948 193.995 265.68 194.265 ;
     RECT  2.16 194.535 64.044 194.805 ;
     RECT  240.948 194.535 265.68 194.805 ;
     RECT  2.16 195.075 64.044 195.345 ;
     RECT  240.948 195.075 265.68 195.345 ;
     RECT  2.16 195.615 64.044 195.885 ;
     RECT  240.948 195.615 265.68 195.885 ;
     RECT  2.16 196.155 64.044 196.425 ;
     RECT  240.948 196.155 265.68 196.425 ;
     RECT  2.16 196.695 64.044 196.965 ;
     RECT  240.948 196.695 265.68 196.965 ;
     RECT  2.16 197.235 64.044 197.505 ;
     RECT  240.948 197.235 265.68 197.505 ;
     RECT  2.16 197.775 64.044 198.045 ;
     RECT  240.948 197.775 265.68 198.045 ;
     RECT  2.16 198.315 64.044 198.585 ;
     RECT  240.948 198.315 265.68 198.585 ;
     RECT  2.16 198.855 265.68 199.125 ;
     RECT  2.16 199.395 265.68 199.665 ;
     RECT  2.16 199.935 265.68 200.205 ;
     RECT  2.16 200.475 265.68 200.745 ;
     RECT  2.16 201.015 265.68 201.285 ;
     RECT  2.16 201.555 265.68 201.825 ;
     RECT  2.16 202.095 265.68 202.365 ;
     RECT  2.16 202.635 265.68 202.905 ;
     RECT  2.16 203.175 265.68 203.445 ;
     RECT  2.16 203.715 265.68 203.985 ;
     RECT  2.16 204.255 265.68 204.525 ;
     RECT  2.16 204.795 265.68 205.065 ;
     RECT  2.16 205.335 265.68 205.605 ;
     RECT  2.16 205.875 265.68 206.145 ;
     RECT  2.16 206.415 265.68 206.685 ;
     RECT  2.16 206.955 265.68 207.225 ;
     RECT  2.16 207.495 265.68 207.765 ;
     RECT  2.16 208.035 265.68 208.305 ;
     RECT  2.16 208.575 265.68 208.845 ;
     RECT  2.16 209.115 265.68 209.385 ;
     RECT  2.16 209.655 265.68 209.925 ;
     RECT  2.16 210.195 265.68 210.465 ;
     RECT  2.16 210.735 265.68 211.005 ;
     RECT  2.16 211.275 265.68 211.545 ;
     RECT  2.16 211.815 265.68 212.085 ;
     RECT  2.16 212.355 265.68 212.625 ;
     RECT  2.16 212.895 265.68 213.165 ;
     RECT  2.16 213.435 265.68 213.705 ;
     RECT  2.16 213.975 265.68 214.245 ;
     RECT  2.16 214.515 265.68 214.785 ;
     RECT  2.16 215.055 265.68 215.325 ;
     RECT  2.16 215.595 265.68 215.865 ;
     RECT  2.16 216.135 265.68 216.405 ;
     RECT  2.16 216.675 265.68 216.945 ;
     RECT  2.16 217.215 265.68 217.485 ;
     RECT  2.16 217.755 265.68 218.025 ;
    LAYER M1 ;
     RECT  2.16 2.151 265.68 21.609 ;
     RECT  2.16 21.609 64.044 23.769 ;
     RECT  26.352 28.071 43.632 45.369 ;
     RECT  2.16 23.769 22.14 49.671 ;
     RECT  47.844 23.769 64.044 49.671 ;
     RECT  66.096 23.76 238.896 196.56 ;
     RECT  2.16 49.671 64.044 198.711 ;
     RECT  240.948 21.609 265.68 198.711 ;
     RECT  2.16 198.711 265.68 218.169 ;
    LAYER M2 ;
     RECT  2.16 2.151 22.14 218.169 ;
     RECT  26.352 28.071 43.632 45.369 ;
     RECT  22.14 2.151 47.844 23.769 ;
     RECT  22.14 49.671 47.844 218.169 ;
     RECT  47.844 2.151 64.044 218.169 ;
     RECT  64.044 110.736 64.679 110.754 ;
     RECT  66.096 23.76 238.896 196.56 ;
     RECT  64.044 2.151 240.948 21.609 ;
     RECT  64.044 198.711 240.948 218.169 ;
     RECT  240.948 2.151 265.68 218.169 ;
    LAYER M3 ;
     RECT  36.36 0.571 36.378 1.675 ;
     RECT  2.415 2.143 2.505 2.413 ;
     RECT  7.815 2.143 7.905 2.413 ;
     RECT  13.215 2.143 13.305 2.413 ;
     RECT  18.615 2.143 18.705 2.413 ;
     RECT  24.015 2.143 24.105 2.413 ;
     RECT  29.415 2.143 29.505 2.413 ;
     RECT  34.815 2.143 34.905 2.413 ;
     RECT  40.215 2.143 40.305 2.413 ;
     RECT  45.615 2.143 45.705 2.413 ;
     RECT  51.015 2.143 51.105 2.413 ;
     RECT  56.415 2.143 56.505 2.413 ;
     RECT  61.815 2.143 61.905 2.413 ;
     RECT  67.215 2.143 67.305 2.413 ;
     RECT  72.615 2.143 72.705 2.413 ;
     RECT  78.015 2.143 78.105 2.413 ;
     RECT  83.415 2.143 83.505 2.413 ;
     RECT  88.815 2.143 88.905 2.413 ;
     RECT  94.215 2.143 94.305 2.413 ;
     RECT  99.615 2.143 99.705 2.413 ;
     RECT  105.015 2.143 105.105 2.413 ;
     RECT  110.415 2.143 110.505 2.413 ;
     RECT  115.815 2.143 115.905 2.413 ;
     RECT  121.215 2.143 121.305 2.413 ;
     RECT  126.615 2.143 126.705 2.413 ;
     RECT  132.015 2.143 132.105 2.413 ;
     RECT  137.415 2.143 137.505 2.413 ;
     RECT  142.815 2.143 142.905 2.413 ;
     RECT  148.215 2.143 148.305 2.413 ;
     RECT  153.615 2.143 153.705 2.413 ;
     RECT  159.015 2.143 159.105 2.413 ;
     RECT  164.415 2.143 164.505 2.413 ;
     RECT  169.815 2.143 169.905 2.413 ;
     RECT  175.215 2.143 175.305 2.413 ;
     RECT  180.615 2.143 180.705 2.413 ;
     RECT  186.015 2.143 186.105 2.413 ;
     RECT  191.415 2.143 191.505 2.413 ;
     RECT  196.815 2.143 196.905 2.413 ;
     RECT  202.215 2.143 202.305 2.413 ;
     RECT  207.615 2.143 207.705 2.413 ;
     RECT  213.015 2.143 213.105 2.413 ;
     RECT  218.415 2.143 218.505 2.413 ;
     RECT  223.815 2.143 223.905 2.413 ;
     RECT  229.215 2.143 229.305 2.413 ;
     RECT  234.615 2.143 234.705 2.413 ;
     RECT  240.015 2.143 240.105 2.413 ;
     RECT  245.415 2.143 245.505 2.413 ;
     RECT  250.815 2.143 250.905 2.413 ;
     RECT  256.215 2.143 256.305 2.413 ;
     RECT  261.615 2.143 261.705 2.413 ;
     RECT  40.215 2.413 40.497 3.931 ;
     RECT  31.176 9.691 31.194 11.399 ;
     RECT  36.216 1.675 36.378 11.669 ;
     RECT  36.216 11.669 36.234 11.785 ;
     RECT  40.176 3.931 40.497 11.939 ;
     RECT  36.144 11.785 36.234 12.209 ;
     RECT  36.108 12.325 36.126 12.557 ;
     RECT  37.872 11.947 37.89 17.117 ;
     RECT  67.215 2.413 67.497 21.347 ;
     RECT  72.615 2.413 72.897 21.347 ;
     RECT  78.015 2.413 78.297 21.347 ;
     RECT  83.415 2.413 83.697 21.347 ;
     RECT  88.815 2.413 89.097 21.347 ;
     RECT  94.215 2.413 94.497 21.347 ;
     RECT  99.615 2.413 99.897 21.347 ;
     RECT  105.015 2.413 105.297 21.347 ;
     RECT  110.415 2.413 110.697 21.347 ;
     RECT  115.815 2.413 116.097 21.347 ;
     RECT  121.215 2.413 121.497 21.347 ;
     RECT  126.615 2.413 126.897 21.347 ;
     RECT  132.015 2.413 132.297 21.347 ;
     RECT  137.415 2.413 137.697 21.347 ;
     RECT  142.815 2.413 143.097 21.347 ;
     RECT  148.215 2.413 148.497 21.347 ;
     RECT  153.615 2.413 153.897 21.347 ;
     RECT  159.015 2.413 159.297 21.347 ;
     RECT  164.415 2.413 164.697 21.347 ;
     RECT  169.815 2.413 170.097 21.347 ;
     RECT  175.215 2.413 175.497 21.347 ;
     RECT  180.615 2.413 180.897 21.347 ;
     RECT  186.015 2.413 186.297 21.347 ;
     RECT  191.415 2.413 191.697 21.347 ;
     RECT  196.815 2.413 197.097 21.347 ;
     RECT  202.215 2.413 202.497 21.347 ;
     RECT  207.615 2.413 207.897 21.347 ;
     RECT  213.015 2.413 213.297 21.347 ;
     RECT  218.415 2.413 218.697 21.347 ;
     RECT  223.815 2.413 224.097 21.347 ;
     RECT  229.215 2.413 229.497 21.347 ;
     RECT  234.615 2.413 234.897 21.347 ;
     RECT  240.015 2.413 240.297 21.347 ;
     RECT  67.215 21.347 67.305 21.617 ;
     RECT  72.615 21.347 72.705 21.617 ;
     RECT  78.015 21.347 78.105 21.617 ;
     RECT  83.415 21.347 83.505 21.617 ;
     RECT  88.815 21.347 88.905 21.617 ;
     RECT  94.215 21.347 94.305 21.617 ;
     RECT  99.615 21.347 99.705 21.617 ;
     RECT  105.015 21.347 105.105 21.617 ;
     RECT  110.415 21.347 110.505 21.617 ;
     RECT  115.815 21.347 115.905 21.617 ;
     RECT  121.215 21.347 121.305 21.617 ;
     RECT  126.615 21.347 126.705 21.617 ;
     RECT  132.015 21.347 132.105 21.617 ;
     RECT  137.415 21.347 137.505 21.617 ;
     RECT  142.815 21.347 142.905 21.617 ;
     RECT  148.215 21.347 148.305 21.617 ;
     RECT  153.615 21.347 153.705 21.617 ;
     RECT  159.015 21.347 159.105 21.617 ;
     RECT  164.415 21.347 164.505 21.617 ;
     RECT  169.815 21.347 169.905 21.617 ;
     RECT  175.215 21.347 175.305 21.617 ;
     RECT  180.615 21.347 180.705 21.617 ;
     RECT  186.015 21.347 186.105 21.617 ;
     RECT  191.415 21.347 191.505 21.617 ;
     RECT  196.815 21.347 196.905 21.617 ;
     RECT  202.215 21.347 202.305 21.617 ;
     RECT  207.615 21.347 207.705 21.617 ;
     RECT  213.015 21.347 213.105 21.617 ;
     RECT  218.415 21.347 218.505 21.617 ;
     RECT  223.815 21.347 223.905 21.617 ;
     RECT  229.215 21.347 229.305 21.617 ;
     RECT  234.615 21.347 234.705 21.617 ;
     RECT  240.015 21.347 240.105 21.617 ;
     RECT  24.015 2.413 24.297 23.507 ;
     RECT  29.415 2.413 29.697 23.507 ;
     RECT  34.815 2.413 35.097 23.507 ;
     RECT  40.215 11.939 40.497 23.507 ;
     RECT  45.615 2.413 45.897 23.507 ;
     RECT  24.015 23.507 24.105 23.777 ;
     RECT  29.415 23.507 29.505 23.777 ;
     RECT  34.815 23.507 34.905 23.777 ;
     RECT  40.215 23.507 40.305 23.777 ;
     RECT  45.615 23.507 45.705 23.777 ;
     RECT  32.976 11.515 32.994 25.853 ;
     RECT  36.036 26.011 36.414 26.059 ;
     RECT  36.036 26.059 36.81 28.063 ;
     RECT  36.036 28.063 37.497 28.291 ;
     RECT  26.607 28.063 26.697 28.333 ;
     RECT  32.007 28.063 32.097 28.333 ;
     RECT  42.807 28.063 42.897 28.333 ;
     RECT  35.748 28.291 37.782 28.417 ;
     RECT  35.568 28.417 37.782 28.723 ;
     RECT  35.568 28.723 37.818 29.029 ;
     RECT  35.568 29.029 37.89 29.227 ;
     RECT  35.352 29.227 37.89 29.371 ;
     RECT  34.704 29.371 37.89 29.497 ;
     RECT  34.596 29.497 37.89 29.755 ;
     RECT  34.524 29.755 37.89 30.029 ;
     RECT  34.524 30.029 37.818 30.335 ;
     RECT  34.776 30.335 37.818 31.379 ;
     RECT  34.776 31.379 37.689 31.649 ;
     RECT  35.496 31.649 37.689 31.685 ;
     RECT  35.712 31.685 37.689 32.189 ;
     RECT  48.492 31.915 48.51 32.443 ;
     RECT  48.348 32.443 48.51 32.459 ;
     RECT  48.348 32.459 48.366 32.495 ;
     RECT  54.828 33.304 54.846 33.341 ;
     RECT  54.612 33.385 54.63 33.437 ;
     RECT  52.344 33.643 52.362 33.781 ;
     RECT  52.056 33.781 52.362 33.809 ;
     RECT  51.015 2.413 51.297 33.925 ;
     RECT  52.056 33.809 52.146 33.925 ;
     RECT  51.015 33.925 52.146 33.965 ;
     RECT  51.015 33.965 51.894 34.205 ;
     RECT  35.712 32.189 36.342 37.589 ;
     RECT  35.712 37.589 36.162 37.733 ;
     RECT  34.632 44.455 34.65 44.491 ;
     RECT  34.632 44.491 34.794 44.761 ;
     RECT  34.632 44.761 34.974 44.879 ;
     RECT  36.144 37.733 36.162 44.879 ;
     RECT  34.632 44.879 34.866 44.995 ;
     RECT  26.607 28.333 26.889 45.107 ;
     RECT  32.007 28.333 32.289 45.107 ;
     RECT  37.407 32.189 37.689 45.107 ;
     RECT  42.807 28.333 43.089 45.107 ;
     RECT  34.488 44.995 34.866 45.149 ;
     RECT  34.488 45.149 34.686 45.185 ;
     RECT  34.488 45.185 34.65 45.245 ;
     RECT  34.488 45.245 34.506 45.293 ;
     RECT  26.607 45.107 26.697 45.377 ;
     RECT  32.007 45.107 32.097 45.377 ;
     RECT  37.407 45.107 37.497 45.377 ;
     RECT  42.807 45.107 42.897 45.377 ;
     RECT  34.344 46.987 34.362 47.179 ;
     RECT  34.344 47.179 34.434 47.309 ;
     RECT  34.416 47.309 34.434 47.371 ;
     RECT  34.416 47.371 34.614 47.405 ;
     RECT  34.596 47.405 34.614 47.611 ;
     RECT  34.596 47.611 34.758 47.645 ;
     RECT  34.74 47.645 34.758 47.741 ;
     RECT  24.015 49.663 24.105 49.933 ;
     RECT  29.415 49.663 29.505 49.933 ;
     RECT  34.815 49.663 34.905 49.933 ;
     RECT  40.215 49.663 40.305 49.933 ;
     RECT  45.615 49.663 45.705 49.933 ;
     RECT  66.096 23.76 238.896 98.251 ;
     RECT  65.988 98.251 238.896 98.381 ;
     RECT  64.656 85.963 64.674 110.759 ;
     RECT  61.815 2.413 62.097 110.767 ;
     RECT  61.812 110.767 62.097 110.813 ;
     RECT  54.9 98.347 54.918 112.649 ;
     RECT  66.096 98.381 238.896 147.307 ;
     RECT  65.988 147.307 238.896 147.437 ;
     RECT  66.096 147.437 238.896 196.56 ;
     RECT  67.215 198.703 67.305 198.973 ;
     RECT  72.615 198.703 72.705 198.973 ;
     RECT  78.015 198.703 78.105 198.973 ;
     RECT  83.415 198.703 83.505 198.973 ;
     RECT  88.815 198.703 88.905 198.973 ;
     RECT  94.215 198.703 94.305 198.973 ;
     RECT  99.615 198.703 99.705 198.973 ;
     RECT  105.015 198.703 105.105 198.973 ;
     RECT  110.415 198.703 110.505 198.973 ;
     RECT  115.815 198.703 115.905 198.973 ;
     RECT  121.215 198.703 121.305 198.973 ;
     RECT  126.615 198.703 126.705 198.973 ;
     RECT  132.015 198.703 132.105 198.973 ;
     RECT  137.415 198.703 137.505 198.973 ;
     RECT  142.815 198.703 142.905 198.973 ;
     RECT  148.215 198.703 148.305 198.973 ;
     RECT  153.615 198.703 153.705 198.973 ;
     RECT  159.015 198.703 159.105 198.973 ;
     RECT  164.415 198.703 164.505 198.973 ;
     RECT  169.815 198.703 169.905 198.973 ;
     RECT  175.215 198.703 175.305 198.973 ;
     RECT  180.615 198.703 180.705 198.973 ;
     RECT  186.015 198.703 186.105 198.973 ;
     RECT  191.415 198.703 191.505 198.973 ;
     RECT  196.815 198.703 196.905 198.973 ;
     RECT  202.215 198.703 202.305 198.973 ;
     RECT  207.615 198.703 207.705 198.973 ;
     RECT  213.015 198.703 213.105 198.973 ;
     RECT  218.415 198.703 218.505 198.973 ;
     RECT  223.815 198.703 223.905 198.973 ;
     RECT  229.215 198.703 229.305 198.973 ;
     RECT  234.615 198.703 234.705 198.973 ;
     RECT  240.015 198.703 240.105 198.973 ;
     RECT  2.415 2.413 2.697 217.907 ;
     RECT  7.815 2.413 8.097 217.907 ;
     RECT  13.215 2.413 13.497 217.907 ;
     RECT  18.615 2.413 18.897 217.907 ;
     RECT  24.015 49.933 24.297 217.907 ;
     RECT  29.415 49.933 29.697 217.907 ;
     RECT  34.815 49.933 35.097 217.907 ;
     RECT  40.215 49.933 40.497 217.907 ;
     RECT  45.615 49.933 45.897 217.907 ;
     RECT  51.015 34.205 51.297 217.907 ;
     RECT  56.415 2.413 56.697 217.907 ;
     RECT  61.815 110.813 62.097 217.907 ;
     RECT  67.215 198.973 67.497 217.907 ;
     RECT  72.615 198.973 72.897 217.907 ;
     RECT  78.015 198.973 78.297 217.907 ;
     RECT  83.415 198.973 83.697 217.907 ;
     RECT  88.815 198.973 89.097 217.907 ;
     RECT  94.215 198.973 94.497 217.907 ;
     RECT  99.615 198.973 99.897 217.907 ;
     RECT  105.015 198.973 105.297 217.907 ;
     RECT  110.415 198.973 110.697 217.907 ;
     RECT  115.815 198.973 116.097 217.907 ;
     RECT  121.215 198.973 121.497 217.907 ;
     RECT  126.615 198.973 126.897 217.907 ;
     RECT  132.015 198.973 132.297 217.907 ;
     RECT  137.415 198.973 137.697 217.907 ;
     RECT  142.815 198.973 143.097 217.907 ;
     RECT  148.215 198.973 148.497 217.907 ;
     RECT  153.615 198.973 153.897 217.907 ;
     RECT  159.015 198.973 159.297 217.907 ;
     RECT  164.415 198.973 164.697 217.907 ;
     RECT  169.815 198.973 170.097 217.907 ;
     RECT  175.215 198.973 175.497 217.907 ;
     RECT  180.615 198.973 180.897 217.907 ;
     RECT  186.015 198.973 186.297 217.907 ;
     RECT  191.415 198.973 191.697 217.907 ;
     RECT  196.815 198.973 197.097 217.907 ;
     RECT  202.215 198.973 202.497 217.907 ;
     RECT  207.615 198.973 207.897 217.907 ;
     RECT  213.015 198.973 213.297 217.907 ;
     RECT  218.415 198.973 218.697 217.907 ;
     RECT  223.815 198.973 224.097 217.907 ;
     RECT  229.215 198.973 229.497 217.907 ;
     RECT  234.615 198.973 234.897 217.907 ;
     RECT  240.015 198.973 240.297 217.907 ;
     RECT  245.415 2.413 245.697 217.907 ;
     RECT  250.815 2.413 251.097 217.907 ;
     RECT  256.215 2.413 256.497 217.907 ;
     RECT  261.615 2.413 261.897 217.907 ;
     RECT  2.415 217.907 2.505 218.177 ;
     RECT  7.815 217.907 7.905 218.177 ;
     RECT  13.215 217.907 13.305 218.177 ;
     RECT  18.615 217.907 18.705 218.177 ;
     RECT  24.015 217.907 24.105 218.177 ;
     RECT  29.415 217.907 29.505 218.177 ;
     RECT  34.815 217.907 34.905 218.177 ;
     RECT  40.215 217.907 40.305 218.177 ;
     RECT  45.615 217.907 45.705 218.177 ;
     RECT  51.015 217.907 51.105 218.177 ;
     RECT  56.415 217.907 56.505 218.177 ;
     RECT  61.815 217.907 61.905 218.177 ;
     RECT  67.215 217.907 67.305 218.177 ;
     RECT  72.615 217.907 72.705 218.177 ;
     RECT  78.015 217.907 78.105 218.177 ;
     RECT  83.415 217.907 83.505 218.177 ;
     RECT  88.815 217.907 88.905 218.177 ;
     RECT  94.215 217.907 94.305 218.177 ;
     RECT  99.615 217.907 99.705 218.177 ;
     RECT  105.015 217.907 105.105 218.177 ;
     RECT  110.415 217.907 110.505 218.177 ;
     RECT  115.815 217.907 115.905 218.177 ;
     RECT  121.215 217.907 121.305 218.177 ;
     RECT  126.615 217.907 126.705 218.177 ;
     RECT  132.015 217.907 132.105 218.177 ;
     RECT  137.415 217.907 137.505 218.177 ;
     RECT  142.815 217.907 142.905 218.177 ;
     RECT  148.215 217.907 148.305 218.177 ;
     RECT  153.615 217.907 153.705 218.177 ;
     RECT  159.015 217.907 159.105 218.177 ;
     RECT  164.415 217.907 164.505 218.177 ;
     RECT  169.815 217.907 169.905 218.177 ;
     RECT  175.215 217.907 175.305 218.177 ;
     RECT  180.615 217.907 180.705 218.177 ;
     RECT  186.015 217.907 186.105 218.177 ;
     RECT  191.415 217.907 191.505 218.177 ;
     RECT  196.815 217.907 196.905 218.177 ;
     RECT  202.215 217.907 202.305 218.177 ;
     RECT  207.615 217.907 207.705 218.177 ;
     RECT  213.015 217.907 213.105 218.177 ;
     RECT  218.415 217.907 218.505 218.177 ;
     RECT  223.815 217.907 223.905 218.177 ;
     RECT  229.215 217.907 229.305 218.177 ;
     RECT  234.615 217.907 234.705 218.177 ;
     RECT  240.015 217.907 240.105 218.177 ;
     RECT  245.415 217.907 245.505 218.177 ;
     RECT  250.815 217.907 250.905 218.177 ;
     RECT  256.215 217.907 256.305 218.177 ;
     RECT  261.615 217.907 261.705 218.177 ;
     RECT  58.968 112.657 58.986 219.485 ;
    LAYER M4 ;
     RECT  2.408 2.148 2.512 218.172 ;
     RECT  2.512 2.418 2.704 217.902 ;
     RECT  7.808 2.148 7.912 218.172 ;
     RECT  7.912 2.418 8.104 217.902 ;
     RECT  13.208 2.148 13.312 218.172 ;
     RECT  13.312 2.418 13.504 217.902 ;
     RECT  18.608 2.148 18.712 218.172 ;
     RECT  18.712 2.418 18.904 217.902 ;
     RECT  24.008 2.148 24.112 23.772 ;
     RECT  24.008 49.668 24.112 218.172 ;
     RECT  24.112 2.418 24.304 23.502 ;
     RECT  24.112 49.938 24.304 217.902 ;
     RECT  26.6 28.068 26.704 45.372 ;
     RECT  26.704 28.338 26.896 45.102 ;
     RECT  29.408 2.148 29.512 23.772 ;
     RECT  29.408 49.668 29.512 218.172 ;
     RECT  29.512 2.418 29.704 23.502 ;
     RECT  29.512 49.938 29.704 217.902 ;
     RECT  31.121 9.696 31.205 9.72 ;
     RECT  32 28.068 32.104 45.372 ;
     RECT  32.104 28.338 32.296 45.102 ;
     RECT  33.973 47.088 34.309 47.304 ;
     RECT  34.309 47.088 34.316 47.64 ;
     RECT  34.213 29.856 34.357 29.88 ;
     RECT  34.316 46.992 34.403 47.64 ;
     RECT  34.403 47.088 34.405 47.64 ;
     RECT  34.357 29.856 34.513 30.36 ;
     RECT  34.477 45.264 34.56 45.288 ;
     RECT  34.56 45.216 34.561 45.288 ;
     RECT  34.561 45.216 34.661 45.24 ;
     RECT  34.513 29.76 34.693 30.36 ;
     RECT  34.405 47.088 34.739 47.736 ;
     RECT  34.739 47.616 34.769 47.736 ;
     RECT  34.597 98.352 34.808 98.376 ;
     RECT  34.501 147.312 34.808 147.336 ;
     RECT  34.769 47.616 34.835 47.64 ;
     RECT  34.808 2.148 34.912 23.772 ;
     RECT  34.808 49.668 34.912 218.172 ;
     RECT  34.693 29.76 34.945 30.456 ;
     RECT  34.912 2.418 35.104 23.502 ;
     RECT  34.912 49.938 35.104 217.902 ;
     RECT  34.069 31.536 35.365 31.56 ;
     RECT  34.945 29.76 35.557 30.552 ;
     RECT  35.557 29.328 35.705 30.552 ;
     RECT  32.965 25.824 36.025 25.848 ;
     RECT  36.025 25.824 36.083 26.04 ;
     RECT  36.083 26.016 36.108 26.04 ;
     RECT  36.097 12.528 36.133 12.552 ;
     RECT  35.365 31.536 36.137 31.704 ;
     RECT  36.188 1.68 36.275 1.704 ;
     RECT  36.133 12 36.275 12.552 ;
     RECT  36.275 12 36.371 12.024 ;
     RECT  35.941 0.576 36.389 0.6 ;
     RECT  36.108 26.016 36.425 26.088 ;
     RECT  36.425 26.064 36.821 26.088 ;
     RECT  35.705 29.328 37.4 29.88 ;
     RECT  37.4 28.068 37.504 45.372 ;
     RECT  37.504 28.338 37.696 45.102 ;
     RECT  36.133 17.088 37.901 17.112 ;
     RECT  40.165 3.936 40.208 3.96 ;
     RECT  35.104 98.352 40.208 98.376 ;
     RECT  35.104 147.312 40.208 147.336 ;
     RECT  40.208 2.148 40.312 23.772 ;
     RECT  40.208 49.668 40.312 218.172 ;
     RECT  40.312 2.418 40.504 23.502 ;
     RECT  40.312 49.938 40.504 217.902 ;
     RECT  40.504 3.936 40.883 3.96 ;
     RECT  42.8 28.068 42.904 45.372 ;
     RECT  42.904 28.338 43.096 45.102 ;
     RECT  40.504 98.352 45.608 98.376 ;
     RECT  40.504 147.312 45.608 147.336 ;
     RECT  45.608 2.148 45.712 23.772 ;
     RECT  45.608 49.668 45.712 218.172 ;
     RECT  45.712 2.418 45.904 23.502 ;
     RECT  45.712 49.938 45.904 217.902 ;
     RECT  48.037 31.92 48.332 31.944 ;
     RECT  48.332 31.92 48.419 32.472 ;
     RECT  48.419 31.92 48.521 31.944 ;
     RECT  45.904 98.352 51.008 98.376 ;
     RECT  45.904 147.312 51.008 147.336 ;
     RECT  51.008 2.148 51.112 218.172 ;
     RECT  51.112 2.418 51.304 217.902 ;
     RECT  51.304 33.792 51.949 34.2 ;
     RECT  51.304 42.768 52.019 42.792 ;
     RECT  51.949 33.792 52.163 33.96 ;
     RECT  52.163 33.792 52.333 33.816 ;
     RECT  52.333 33.648 52.451 33.816 ;
     RECT  52.451 33.648 52.883 33.672 ;
     RECT  54.572 33.408 54.659 33.432 ;
     RECT  54.817 33.312 55.283 33.336 ;
     RECT  51.304 98.352 56.408 98.376 ;
     RECT  51.304 147.312 56.408 147.336 ;
     RECT  56.408 2.148 56.512 218.172 ;
     RECT  56.512 2.418 56.704 217.902 ;
     RECT  56.704 98.352 61.808 98.376 ;
     RECT  56.704 110.784 61.808 110.808 ;
     RECT  56.704 147.312 61.808 147.336 ;
     RECT  61.808 2.148 61.912 218.172 ;
     RECT  61.912 2.418 62.104 217.902 ;
     RECT  58.957 219.456 62.387 219.48 ;
     RECT  62.104 98.352 65.977 98.376 ;
     RECT  62.104 147.312 65.977 147.336 ;
     RECT  64.645 85.968 66.168 85.992 ;
     RECT  65.977 98.256 66.168 98.376 ;
     RECT  65.749 110.544 66.168 110.568 ;
     RECT  65.845 122.832 66.168 122.856 ;
     RECT  65.941 135.12 66.168 135.144 ;
     RECT  65.977 147.312 66.168 147.432 ;
     RECT  65.941 159.6 66.168 159.72 ;
     RECT  67.208 2.148 67.312 21.612 ;
     RECT  67.208 198.708 67.312 218.172 ;
     RECT  67.312 2.418 67.504 21.342 ;
     RECT  67.312 198.978 67.504 217.902 ;
     RECT  72.608 2.148 72.712 21.612 ;
     RECT  72.608 198.708 72.712 218.172 ;
     RECT  72.712 2.418 72.904 21.342 ;
     RECT  72.712 198.978 72.904 217.902 ;
     RECT  78.008 2.148 78.112 21.612 ;
     RECT  78.008 198.708 78.112 218.172 ;
     RECT  78.112 2.418 78.304 21.342 ;
     RECT  78.112 198.978 78.304 217.902 ;
     RECT  83.408 2.148 83.512 21.612 ;
     RECT  83.408 198.708 83.512 218.172 ;
     RECT  83.512 2.418 83.704 21.342 ;
     RECT  83.512 198.978 83.704 217.902 ;
     RECT  88.808 2.148 88.912 21.612 ;
     RECT  88.808 198.708 88.912 218.172 ;
     RECT  88.912 2.418 89.104 21.342 ;
     RECT  88.912 198.978 89.104 217.902 ;
     RECT  94.208 2.148 94.312 21.612 ;
     RECT  94.208 198.708 94.312 218.172 ;
     RECT  94.312 2.418 94.504 21.342 ;
     RECT  94.312 198.978 94.504 217.902 ;
     RECT  99.608 2.148 99.712 21.612 ;
     RECT  99.608 198.708 99.712 218.172 ;
     RECT  99.712 2.418 99.904 21.342 ;
     RECT  99.712 198.978 99.904 217.902 ;
     RECT  105.008 2.148 105.112 21.612 ;
     RECT  105.008 198.708 105.112 218.172 ;
     RECT  105.112 2.418 105.304 21.342 ;
     RECT  105.112 198.978 105.304 217.902 ;
     RECT  110.408 2.148 110.512 21.612 ;
     RECT  110.408 198.708 110.512 218.172 ;
     RECT  110.512 2.418 110.704 21.342 ;
     RECT  110.512 198.978 110.704 217.902 ;
     RECT  115.808 2.148 115.912 21.612 ;
     RECT  115.808 198.708 115.912 218.172 ;
     RECT  115.912 2.418 116.104 21.342 ;
     RECT  115.912 198.978 116.104 217.902 ;
     RECT  121.208 2.148 121.312 21.612 ;
     RECT  121.208 198.708 121.312 218.172 ;
     RECT  121.312 2.418 121.504 21.342 ;
     RECT  121.312 198.978 121.504 217.902 ;
     RECT  126.608 2.148 126.712 21.612 ;
     RECT  126.608 198.708 126.712 218.172 ;
     RECT  126.712 2.418 126.904 21.342 ;
     RECT  126.712 198.978 126.904 217.902 ;
     RECT  132.008 2.148 132.112 21.612 ;
     RECT  132.008 198.708 132.112 218.172 ;
     RECT  132.112 2.418 132.304 21.342 ;
     RECT  132.112 198.978 132.304 217.902 ;
     RECT  137.408 2.148 137.512 21.612 ;
     RECT  137.408 198.708 137.512 218.172 ;
     RECT  137.512 2.418 137.704 21.342 ;
     RECT  137.512 198.978 137.704 217.902 ;
     RECT  142.808 2.148 142.912 21.612 ;
     RECT  142.808 198.708 142.912 218.172 ;
     RECT  142.912 2.418 143.104 21.342 ;
     RECT  142.912 198.978 143.104 217.902 ;
     RECT  148.208 2.148 148.312 21.612 ;
     RECT  148.208 198.708 148.312 218.172 ;
     RECT  148.312 2.418 148.504 21.342 ;
     RECT  148.312 198.978 148.504 217.902 ;
     RECT  153.608 2.148 153.712 21.612 ;
     RECT  153.608 198.708 153.712 218.172 ;
     RECT  153.712 2.418 153.904 21.342 ;
     RECT  153.712 198.978 153.904 217.902 ;
     RECT  159.008 2.148 159.112 21.612 ;
     RECT  159.008 198.708 159.112 218.172 ;
     RECT  159.112 2.418 159.304 21.342 ;
     RECT  159.112 198.978 159.304 217.902 ;
     RECT  164.408 2.148 164.512 21.612 ;
     RECT  164.408 198.708 164.512 218.172 ;
     RECT  164.512 2.418 164.704 21.342 ;
     RECT  164.512 198.978 164.704 217.902 ;
     RECT  169.808 2.148 169.912 21.612 ;
     RECT  169.808 198.708 169.912 218.172 ;
     RECT  169.912 2.418 170.104 21.342 ;
     RECT  169.912 198.978 170.104 217.902 ;
     RECT  175.208 2.148 175.312 21.612 ;
     RECT  175.208 198.708 175.312 218.172 ;
     RECT  175.312 2.418 175.504 21.342 ;
     RECT  175.312 198.978 175.504 217.902 ;
     RECT  180.608 2.148 180.712 21.612 ;
     RECT  180.608 198.708 180.712 218.172 ;
     RECT  180.712 2.418 180.904 21.342 ;
     RECT  180.712 198.978 180.904 217.902 ;
     RECT  186.008 2.148 186.112 21.612 ;
     RECT  186.008 198.708 186.112 218.172 ;
     RECT  186.112 2.418 186.304 21.342 ;
     RECT  186.112 198.978 186.304 217.902 ;
     RECT  191.408 2.148 191.512 21.612 ;
     RECT  191.408 198.708 191.512 218.172 ;
     RECT  191.512 2.418 191.704 21.342 ;
     RECT  191.512 198.978 191.704 217.902 ;
     RECT  196.808 2.148 196.912 21.612 ;
     RECT  196.808 198.708 196.912 218.172 ;
     RECT  196.912 2.418 197.104 21.342 ;
     RECT  196.912 198.978 197.104 217.902 ;
     RECT  202.208 2.148 202.312 21.612 ;
     RECT  202.208 198.708 202.312 218.172 ;
     RECT  202.312 2.418 202.504 21.342 ;
     RECT  202.312 198.978 202.504 217.902 ;
     RECT  207.608 2.148 207.712 21.612 ;
     RECT  207.608 198.708 207.712 218.172 ;
     RECT  207.712 2.418 207.904 21.342 ;
     RECT  207.712 198.978 207.904 217.902 ;
     RECT  213.008 2.148 213.112 21.612 ;
     RECT  213.008 198.708 213.112 218.172 ;
     RECT  213.112 2.418 213.304 21.342 ;
     RECT  213.112 198.978 213.304 217.902 ;
     RECT  218.408 2.148 218.512 21.612 ;
     RECT  218.408 198.708 218.512 218.172 ;
     RECT  218.512 2.418 218.704 21.342 ;
     RECT  218.512 198.978 218.704 217.902 ;
     RECT  223.808 2.148 223.912 21.612 ;
     RECT  223.808 198.708 223.912 218.172 ;
     RECT  223.912 2.418 224.104 21.342 ;
     RECT  223.912 198.978 224.104 217.902 ;
     RECT  229.208 2.148 229.312 21.612 ;
     RECT  229.208 198.708 229.312 218.172 ;
     RECT  229.312 2.418 229.504 21.342 ;
     RECT  229.312 198.978 229.504 217.902 ;
     RECT  234.608 2.148 234.712 21.612 ;
     RECT  234.608 198.708 234.712 218.172 ;
     RECT  234.712 2.418 234.904 21.342 ;
     RECT  234.712 198.978 234.904 217.902 ;
     RECT  66.168 23.76 238.824 196.56 ;
     RECT  240.008 2.148 240.112 21.612 ;
     RECT  240.008 198.708 240.112 218.172 ;
     RECT  240.112 2.418 240.304 21.342 ;
     RECT  240.112 198.978 240.304 217.902 ;
     RECT  245.408 2.148 245.512 218.172 ;
     RECT  245.512 2.418 245.704 217.902 ;
     RECT  250.808 2.148 250.912 218.172 ;
     RECT  250.912 2.418 251.104 217.902 ;
     RECT  256.208 2.148 256.312 218.172 ;
     RECT  256.312 2.418 256.504 217.902 ;
     RECT  261.608 2.148 261.712 218.172 ;
     RECT  261.712 2.418 261.904 217.902 ;
    LAYER M5 ;
     RECT  35.952 0.016 36.264 0.611 ;
     RECT  36.24 0.611 36.264 1.715 ;
     RECT  40.848 0.016 40.872 2.137 ;
     RECT  62.448 0.016 62.472 2.137 ;
     RECT  2.4 2.137 2.52 2.407 ;
     RECT  7.8 2.137 7.92 2.407 ;
     RECT  13.2 2.137 13.32 2.407 ;
     RECT  18.6 2.137 18.72 2.407 ;
     RECT  24 2.137 24.12 2.407 ;
     RECT  29.4 2.137 29.52 2.407 ;
     RECT  34.8 2.137 34.92 2.407 ;
     RECT  45.6 2.137 45.72 2.407 ;
     RECT  51 2.137 51.12 2.407 ;
     RECT  56.4 2.137 56.52 2.407 ;
     RECT  57.648 0.016 57.672 2.407 ;
     RECT  67.2 2.137 67.32 2.407 ;
     RECT  72.6 2.137 72.72 2.407 ;
     RECT  78 2.137 78.12 2.407 ;
     RECT  83.4 2.137 83.52 2.407 ;
     RECT  88.8 2.137 88.92 2.407 ;
     RECT  94.2 2.137 94.32 2.407 ;
     RECT  99.6 2.137 99.72 2.407 ;
     RECT  105 2.137 105.12 2.407 ;
     RECT  110.4 2.137 110.52 2.407 ;
     RECT  115.8 2.137 115.92 2.407 ;
     RECT  121.2 2.137 121.32 2.407 ;
     RECT  126.6 2.137 126.72 2.407 ;
     RECT  132 2.137 132.12 2.407 ;
     RECT  137.4 2.137 137.52 2.407 ;
     RECT  142.8 2.137 142.92 2.407 ;
     RECT  148.2 2.137 148.32 2.407 ;
     RECT  153.6 2.137 153.72 2.407 ;
     RECT  159 2.137 159.12 2.407 ;
     RECT  164.4 2.137 164.52 2.407 ;
     RECT  169.8 2.137 169.92 2.407 ;
     RECT  175.2 2.137 175.32 2.407 ;
     RECT  180.6 2.137 180.72 2.407 ;
     RECT  186 2.137 186.12 2.407 ;
     RECT  191.4 2.137 191.52 2.407 ;
     RECT  196.8 2.137 196.92 2.407 ;
     RECT  202.2 2.137 202.32 2.407 ;
     RECT  207.6 2.137 207.72 2.407 ;
     RECT  213 2.137 213.12 2.407 ;
     RECT  218.4 2.137 218.52 2.407 ;
     RECT  223.8 2.137 223.92 2.407 ;
     RECT  229.2 2.137 229.32 2.407 ;
     RECT  234.6 2.137 234.72 2.407 ;
     RECT  240 2.137 240.12 2.407 ;
     RECT  245.4 2.137 245.52 2.407 ;
     RECT  250.8 2.137 250.92 2.407 ;
     RECT  256.2 2.137 256.32 2.407 ;
     RECT  261.6 2.137 261.72 2.407 ;
     RECT  40.2 2.137 40.872 3.971 ;
     RECT  31.152 0.016 31.176 9.731 ;
     RECT  36.336 11.989 36.36 12.517 ;
     RECT  36.24 12.517 36.36 17.077 ;
     RECT  34.8 2.407 35.112 23.513 ;
     RECT  34.8 23.513 34.92 23.783 ;
     RECT  36.144 17.077 36.36 25.813 ;
     RECT  36.048 25.813 36.36 26.051 ;
     RECT  36.144 26.051 36.36 26.099 ;
     RECT  26.592 28.057 26.712 28.071 ;
     RECT  31.992 28.057 32.112 28.071 ;
     RECT  37.392 28.057 37.512 28.071 ;
     RECT  42.792 28.057 42.912 28.071 ;
     RECT  35.376 29.749 35.4 29.845 ;
     RECT  34.224 29.845 35.4 31.525 ;
     RECT  34.08 31.525 35.4 31.715 ;
     RECT  48.048 0.016 48.072 31.955 ;
     RECT  61.8 2.137 62.472 33.323 ;
     RECT  55.248 33.263 55.272 33.347 ;
     RECT  52.848 0.016 52.872 33.683 ;
     RECT  56.4 2.407 57.672 33.835 ;
     RECT  52.416 33.781 52.44 33.865 ;
     RECT  51 2.407 51.312 33.925 ;
     RECT  26.592 28.071 26.904 45.369 ;
     RECT  31.992 28.071 32.304 45.369 ;
     RECT  37.392 28.071 37.704 45.369 ;
     RECT  42.792 28.071 43.104 45.369 ;
     RECT  26.592 45.369 26.712 45.383 ;
     RECT  31.992 45.369 32.112 45.383 ;
     RECT  37.392 45.369 37.512 45.383 ;
     RECT  42.792 45.369 42.912 45.383 ;
     RECT  34.08 31.715 34.728 47.077 ;
     RECT  33.984 47.077 34.728 47.285 ;
     RECT  54.624 33.397 54.648 47.285 ;
     RECT  33.984 47.285 34.824 47.315 ;
     RECT  51 33.925 52.152 47.339 ;
     RECT  54.624 47.285 54.744 47.349 ;
     RECT  51 47.339 52.008 47.403 ;
     RECT  48.384 32.437 48.408 47.595 ;
     RECT  65.952 47.541 65.976 47.605 ;
     RECT  34.032 47.315 34.824 47.651 ;
     RECT  34.032 47.651 34.776 47.659 ;
     RECT  54.624 47.349 54.84 47.659 ;
     RECT  65.856 47.605 65.976 47.669 ;
     RECT  54.624 47.659 54.744 47.723 ;
     RECT  65.76 47.669 65.976 47.733 ;
     RECT  34.416 47.659 34.632 47.747 ;
     RECT  54.624 47.723 54.648 47.787 ;
     RECT  34.512 47.747 34.632 49.657 ;
     RECT  34.512 49.657 34.92 49.927 ;
     RECT  65.76 47.733 66.072 110.579 ;
     RECT  56.4 33.835 56.712 110.773 ;
     RECT  65.856 110.579 66.072 122.867 ;
     RECT  65.952 122.867 66.072 135.155 ;
     RECT  34.512 49.927 35.112 147.347 ;
     RECT  66.048 135.155 66.072 159.589 ;
     RECT  65.952 159.589 66.072 159.635 ;
     RECT  65.952 159.635 65.976 159.731 ;
     RECT  2.4 2.407 2.712 217.913 ;
     RECT  7.8 2.407 8.112 217.913 ;
     RECT  13.2 2.407 13.512 217.913 ;
     RECT  18.6 2.407 18.912 217.913 ;
     RECT  24 2.407 24.312 217.913 ;
     RECT  29.4 2.407 29.712 217.913 ;
     RECT  34.8 147.347 35.112 217.913 ;
     RECT  40.2 3.971 40.512 217.913 ;
     RECT  45.6 2.407 45.912 217.913 ;
     RECT  51 47.403 51.312 217.913 ;
     RECT  56.4 110.773 57.576 217.913 ;
     RECT  61.8 33.323 62.112 217.913 ;
     RECT  67.2 2.407 67.512 217.913 ;
     RECT  72.6 2.407 72.912 217.913 ;
     RECT  78 2.407 78.312 217.913 ;
     RECT  83.4 2.407 83.712 217.913 ;
     RECT  88.8 2.407 89.112 217.913 ;
     RECT  94.2 2.407 94.512 217.913 ;
     RECT  99.6 2.407 99.912 217.913 ;
     RECT  105 2.407 105.312 217.913 ;
     RECT  110.4 2.407 110.712 217.913 ;
     RECT  115.8 2.407 116.112 217.913 ;
     RECT  121.2 2.407 121.512 217.913 ;
     RECT  126.6 2.407 126.912 217.913 ;
     RECT  132 2.407 132.312 217.913 ;
     RECT  137.4 2.407 137.712 217.913 ;
     RECT  142.8 2.407 143.112 217.913 ;
     RECT  148.2 2.407 148.512 217.913 ;
     RECT  153.6 2.407 153.912 217.913 ;
     RECT  159 2.407 159.312 217.913 ;
     RECT  164.4 2.407 164.712 217.913 ;
     RECT  169.8 2.407 170.112 217.913 ;
     RECT  175.2 2.407 175.512 217.913 ;
     RECT  180.6 2.407 180.912 217.913 ;
     RECT  186 2.407 186.312 217.913 ;
     RECT  191.4 2.407 191.712 217.913 ;
     RECT  196.8 2.407 197.112 217.913 ;
     RECT  202.2 2.407 202.512 217.913 ;
     RECT  207.6 2.407 207.912 217.913 ;
     RECT  213 2.407 213.312 217.913 ;
     RECT  218.4 2.407 218.712 217.913 ;
     RECT  223.8 2.407 224.112 217.913 ;
     RECT  229.2 2.407 229.512 217.913 ;
     RECT  234.6 2.407 234.912 217.913 ;
     RECT  240 2.407 240.312 217.913 ;
     RECT  245.4 2.407 245.712 217.913 ;
     RECT  250.8 2.407 251.112 217.913 ;
     RECT  256.2 2.407 256.512 217.913 ;
     RECT  261.6 2.407 261.912 217.913 ;
     RECT  2.4 217.913 2.52 218.183 ;
     RECT  7.8 217.913 7.92 218.183 ;
     RECT  13.2 217.913 13.32 218.183 ;
     RECT  18.6 217.913 18.72 218.183 ;
     RECT  24 217.913 24.12 218.183 ;
     RECT  29.4 217.913 29.52 218.183 ;
     RECT  34.8 217.913 34.92 218.183 ;
     RECT  40.2 217.913 40.32 218.183 ;
     RECT  45.6 217.913 45.72 218.183 ;
     RECT  51 217.913 51.12 218.183 ;
     RECT  56.4 217.913 56.52 218.183 ;
     RECT  61.8 217.913 61.92 218.183 ;
     RECT  67.2 217.913 67.32 218.183 ;
     RECT  72.6 217.913 72.72 218.183 ;
     RECT  78 217.913 78.12 218.183 ;
     RECT  83.4 217.913 83.52 218.183 ;
     RECT  88.8 217.913 88.92 218.183 ;
     RECT  94.2 217.913 94.32 218.183 ;
     RECT  99.6 217.913 99.72 218.183 ;
     RECT  105 217.913 105.12 218.183 ;
     RECT  110.4 217.913 110.52 218.183 ;
     RECT  115.8 217.913 115.92 218.183 ;
     RECT  121.2 217.913 121.32 218.183 ;
     RECT  126.6 217.913 126.72 218.183 ;
     RECT  132 217.913 132.12 218.183 ;
     RECT  137.4 217.913 137.52 218.183 ;
     RECT  142.8 217.913 142.92 218.183 ;
     RECT  148.2 217.913 148.32 218.183 ;
     RECT  153.6 217.913 153.72 218.183 ;
     RECT  159 217.913 159.12 218.183 ;
     RECT  164.4 217.913 164.52 218.183 ;
     RECT  169.8 217.913 169.92 218.183 ;
     RECT  175.2 217.913 175.32 218.183 ;
     RECT  180.6 217.913 180.72 218.183 ;
     RECT  186 217.913 186.12 218.183 ;
     RECT  191.4 217.913 191.52 218.183 ;
     RECT  196.8 217.913 196.92 218.183 ;
     RECT  202.2 217.913 202.32 218.183 ;
     RECT  207.6 217.913 207.72 218.183 ;
     RECT  213 217.913 213.12 218.183 ;
     RECT  218.4 217.913 218.52 218.183 ;
     RECT  223.8 217.913 223.92 218.183 ;
     RECT  229.2 217.913 229.32 218.183 ;
     RECT  234.6 217.913 234.72 218.183 ;
     RECT  240 217.913 240.12 218.183 ;
     RECT  245.4 217.913 245.52 218.183 ;
     RECT  250.8 217.913 250.92 218.183 ;
     RECT  256.2 217.913 256.32 218.183 ;
     RECT  261.6 217.913 261.72 218.183 ;
     RECT  57.552 217.913 57.576 220.304 ;
     RECT  62.352 219.445 62.376 220.304 ;
    LAYER M6 ;
     RECT  2.4 2.529 2.592 2.817 ;
     RECT  2.4 7.929 2.592 8.217 ;
     RECT  2.4 13.329 2.592 13.617 ;
     RECT  2.4 18.729 2.592 19.017 ;
     RECT  2.4 24.129 2.592 24.417 ;
     RECT  2.4 29.529 2.592 29.817 ;
     RECT  2.4 34.929 2.592 35.217 ;
     RECT  2.4 40.329 2.592 40.617 ;
     RECT  2.4 45.729 2.592 46.017 ;
     RECT  2.4 51.129 2.592 51.417 ;
     RECT  2.4 56.529 2.592 56.817 ;
     RECT  2.4 61.929 2.592 62.217 ;
     RECT  2.4 67.329 2.592 67.617 ;
     RECT  2.4 72.729 2.592 73.017 ;
     RECT  2.4 78.129 2.592 78.417 ;
     RECT  2.4 83.529 2.592 83.817 ;
     RECT  2.4 88.929 2.592 89.217 ;
     RECT  2.4 94.329 2.592 94.617 ;
     RECT  2.4 99.729 2.592 100.017 ;
     RECT  2.4 105.129 2.592 105.417 ;
     RECT  2.4 110.529 2.592 110.817 ;
     RECT  2.4 115.929 2.592 116.217 ;
     RECT  2.4 121.329 2.592 121.617 ;
     RECT  2.4 126.729 2.592 127.017 ;
     RECT  2.4 132.129 2.592 132.417 ;
     RECT  2.4 137.529 2.592 137.817 ;
     RECT  2.4 142.929 2.592 143.217 ;
     RECT  2.4 148.329 2.592 148.617 ;
     RECT  2.4 153.729 2.592 154.017 ;
     RECT  2.4 159.129 2.592 159.417 ;
     RECT  2.4 164.529 2.592 164.817 ;
     RECT  2.4 169.929 2.592 170.217 ;
     RECT  2.4 175.329 2.592 175.617 ;
     RECT  2.4 180.729 2.592 181.017 ;
     RECT  2.4 186.129 2.592 186.417 ;
     RECT  2.4 191.529 2.592 191.817 ;
     RECT  2.4 196.929 2.592 197.217 ;
     RECT  2.4 202.329 2.592 202.617 ;
     RECT  2.4 207.729 2.592 208.017 ;
     RECT  2.4 213.129 2.592 213.417 ;
     RECT  2.592 45.729 34.021 46.401 ;
     RECT  34.021 45.729 34.787 47.648 ;
     RECT  34.787 45.729 48.373 47.52 ;
     RECT  2.592 34.929 52.405 35.601 ;
     RECT  48.373 45.729 54.613 47.584 ;
     RECT  52.405 33.792 55.237 35.601 ;
     RECT  55.237 33.28 57.683 35.601 ;
     RECT  57.683 33.28 62.483 33.312 ;
     RECT  54.613 45.729 65.987 47.776 ;
     RECT  65.987 47.744 66.083 47.776 ;
     RECT  2.592 2.529 261.912 3.201 ;
     RECT  2.592 7.929 261.912 8.601 ;
     RECT  2.592 13.329 261.912 14.001 ;
     RECT  2.592 18.729 261.912 19.401 ;
     RECT  2.592 24.129 261.912 24.801 ;
     RECT  2.592 29.529 261.912 30.201 ;
     RECT  57.683 34.929 261.912 35.601 ;
     RECT  2.592 40.329 261.912 41.001 ;
     RECT  65.987 45.729 261.912 46.401 ;
     RECT  2.592 51.129 261.912 51.801 ;
     RECT  2.592 56.529 261.912 57.201 ;
     RECT  2.592 61.929 261.912 62.601 ;
     RECT  2.592 67.329 261.912 68.001 ;
     RECT  2.592 72.729 261.912 73.401 ;
     RECT  2.592 78.129 261.912 78.801 ;
     RECT  2.592 83.529 261.912 84.201 ;
     RECT  2.592 88.929 261.912 89.601 ;
     RECT  2.592 94.329 261.912 95.001 ;
     RECT  2.592 99.729 261.912 100.401 ;
     RECT  2.592 105.129 261.912 105.801 ;
     RECT  2.592 110.529 261.912 111.201 ;
     RECT  2.592 115.929 261.912 116.601 ;
     RECT  2.592 121.329 261.912 122.001 ;
     RECT  2.592 126.729 261.912 127.401 ;
     RECT  2.592 132.129 261.912 132.801 ;
     RECT  2.592 137.529 261.912 138.201 ;
     RECT  2.592 142.929 261.912 143.601 ;
     RECT  2.592 148.329 261.912 149.001 ;
     RECT  2.592 153.729 261.912 154.401 ;
     RECT  2.592 159.129 261.912 159.801 ;
     RECT  2.592 164.529 261.912 165.201 ;
     RECT  2.592 169.929 261.912 170.601 ;
     RECT  2.592 175.329 261.912 176.001 ;
     RECT  2.592 180.729 261.912 181.401 ;
     RECT  2.592 186.129 261.912 186.801 ;
     RECT  2.592 191.529 261.912 192.201 ;
     RECT  2.592 196.929 261.912 197.601 ;
     RECT  2.592 202.329 261.912 203.001 ;
     RECT  2.592 207.729 261.912 208.401 ;
     RECT  2.592 213.129 261.912 213.801 ;
     RECT  261.912 2.529 262.504 2.817 ;
     RECT  261.912 7.929 262.504 8.217 ;
     RECT  261.912 13.329 262.504 13.617 ;
     RECT  261.912 18.729 262.504 19.017 ;
     RECT  261.912 24.129 262.504 24.417 ;
     RECT  261.912 29.529 262.504 29.817 ;
     RECT  261.912 34.929 262.504 35.217 ;
     RECT  261.912 40.329 262.504 40.617 ;
     RECT  261.912 45.729 262.504 46.017 ;
     RECT  261.912 51.129 262.504 51.417 ;
     RECT  261.912 56.529 262.504 56.817 ;
     RECT  261.912 61.929 262.504 62.217 ;
     RECT  261.912 67.329 262.504 67.617 ;
     RECT  261.912 72.729 262.504 73.017 ;
     RECT  261.912 78.129 262.504 78.417 ;
     RECT  261.912 83.529 262.504 83.817 ;
     RECT  261.912 88.929 262.504 89.217 ;
     RECT  261.912 94.329 262.504 94.617 ;
     RECT  261.912 99.729 262.504 100.017 ;
     RECT  261.912 105.129 262.504 105.417 ;
     RECT  261.912 110.529 262.504 110.817 ;
     RECT  261.912 115.929 262.504 116.217 ;
     RECT  261.912 121.329 262.504 121.617 ;
     RECT  261.912 126.729 262.504 127.017 ;
     RECT  261.912 132.129 262.504 132.417 ;
     RECT  261.912 137.529 262.504 137.817 ;
     RECT  261.912 142.929 262.504 143.217 ;
     RECT  261.912 148.329 262.504 148.617 ;
     RECT  261.912 153.729 262.504 154.017 ;
     RECT  261.912 159.129 262.504 159.417 ;
     RECT  261.912 164.529 262.504 164.817 ;
     RECT  261.912 169.929 262.504 170.217 ;
     RECT  261.912 175.329 262.504 175.617 ;
     RECT  261.912 180.729 262.504 181.017 ;
     RECT  261.912 186.129 262.504 186.417 ;
     RECT  261.912 191.529 262.504 191.817 ;
     RECT  261.912 196.929 262.504 197.217 ;
     RECT  261.912 202.329 262.504 202.617 ;
     RECT  261.912 207.729 262.504 208.017 ;
     RECT  261.912 213.129 262.504 213.417 ;
    LAYER M7 ;
     RECT  3.016 2.151 3.304 218.169 ;
     RECT  8.416 2.151 8.704 218.169 ;
     RECT  13.816 2.151 14.104 218.169 ;
     RECT  19.216 2.151 19.504 218.169 ;
     RECT  24.616 2.151 24.904 218.169 ;
     RECT  30.016 2.151 30.304 218.169 ;
     RECT  35.416 2.151 35.704 218.169 ;
     RECT  40.816 2.151 41.104 218.169 ;
     RECT  46.216 2.151 46.504 218.169 ;
     RECT  51.616 2.151 51.904 218.169 ;
     RECT  57.016 2.151 57.304 218.169 ;
     RECT  62.416 2.151 62.704 218.169 ;
     RECT  67.816 2.151 68.104 218.169 ;
     RECT  73.216 2.151 73.504 218.169 ;
     RECT  78.616 2.151 78.904 218.169 ;
     RECT  84.016 2.151 84.304 218.169 ;
     RECT  89.416 2.151 89.704 218.169 ;
     RECT  94.816 2.151 95.104 218.169 ;
     RECT  100.216 2.151 100.504 218.169 ;
     RECT  105.616 2.151 105.904 218.169 ;
     RECT  111.016 2.151 111.304 218.169 ;
     RECT  116.416 2.151 116.704 218.169 ;
     RECT  121.816 2.151 122.104 218.169 ;
     RECT  127.216 2.151 127.504 218.169 ;
     RECT  132.616 2.151 132.904 218.169 ;
     RECT  138.016 2.151 138.304 218.169 ;
     RECT  143.416 2.151 143.704 218.169 ;
     RECT  148.816 2.151 149.104 218.169 ;
     RECT  154.216 2.151 154.504 218.169 ;
     RECT  159.616 2.151 159.904 218.169 ;
     RECT  165.016 2.151 165.304 218.169 ;
     RECT  170.416 2.151 170.704 218.169 ;
     RECT  175.816 2.151 176.104 218.169 ;
     RECT  181.216 2.151 181.504 218.169 ;
     RECT  186.616 2.151 186.904 218.169 ;
     RECT  192.016 2.151 192.304 218.169 ;
     RECT  197.416 2.151 197.704 218.169 ;
     RECT  202.816 2.151 203.104 218.169 ;
     RECT  208.216 2.151 208.504 218.169 ;
     RECT  213.616 2.151 213.904 218.169 ;
     RECT  219.016 2.151 219.304 218.169 ;
     RECT  224.416 2.151 224.704 218.169 ;
     RECT  229.816 2.151 230.104 218.169 ;
     RECT  235.216 2.151 235.504 218.169 ;
     RECT  240.616 2.151 240.904 218.169 ;
     RECT  246.016 2.151 246.304 218.169 ;
     RECT  251.416 2.151 251.704 218.169 ;
     RECT  256.816 2.151 257.104 218.169 ;
     RECT  262.216 2.151 262.504 218.169 ;
  END
END hfd_ckgen
END LIBRARY
